VERSION 5.5 ;
NAMESCASESENSITIVE ON ;
BUSBITCHARS "[]" ;
DIVIDERCHAR "/" ;

PROPERTYDEFINITIONS
  LAYER routingPitch REAL ;
END PROPERTYDEFINITIONS

UNITS
  DATABASE MICRONS 1000 ;
END UNITS
MANUFACTURINGGRID 0.01 ;
LAYER POLY1
  TYPE MASTERSLICE ;
END POLY1

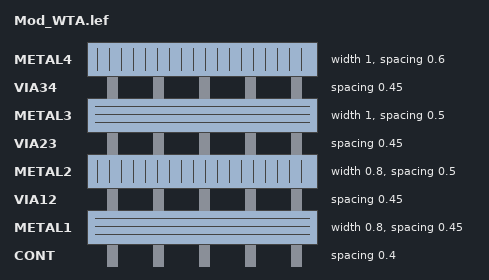
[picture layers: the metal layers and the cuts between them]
LAYER CONT
  TYPE CUT ;
  SPACING 0.4 ;
END CONT

LAYER METAL1
  TYPE ROUTING ;
  DIRECTION HORIZONTAL ;
  PITCH 0 ;
  WIDTH 0.8 ;
  SPACING 0.45 ;
  PROPERTY routingPitch 1.25 ;
END METAL1

LAYER VIA12
  TYPE CUT ;
  SPACING 0.45 ;
END VIA12

LAYER METAL2
  TYPE ROUTING ;
  DIRECTION VERTICAL ;
  PITCH 0 ;
  WIDTH 0.8 ;
  SPACING 0.5 ;
  PROPERTY routingPitch 1.4 ;
END METAL2

LAYER VIA23
  TYPE CUT ;
  SPACING 0.45 ;
END VIA23

LAYER METAL3
  TYPE ROUTING ;
  DIRECTION HORIZONTAL ;
  PITCH 0 ;
  WIDTH 1.0 ;
  SPACING 0.5 ;
  PROPERTY routingPitch 1.25 ;
END METAL3

LAYER VIA34
  TYPE CUT ;
  SPACING 0.45 ;
END VIA34

LAYER METAL4
  TYPE ROUTING ;
  DIRECTION VERTICAL ;
  PITCH 0 ;
  WIDTH 1.0 ;
  SPACING 0.6 ;
  PROPERTY routingPitch 1.4 ;
END METAL4

LAYER OVERLAP
  TYPE OVERLAP ;
END OVERLAP

VIARULE M4_M3 GENERATE
  LAYER METAL3 ;
    ENCLOSURE 0.2 0.2 ;
  LAYER METAL4 ;
    ENCLOSURE 0.15 0.15 ;
  LAYER VIA34 ;
    RECT -0.25 -0.25 0.25 0.25 ;
    SPACING 1 BY 1 ;
END M4_M3

VIARULE M3_M2 GENERATE
  LAYER METAL2 ;
    ENCLOSURE 0.2 0.2 ;
  LAYER METAL3 ;
    ENCLOSURE 0.15 0.15 ;
  LAYER VIA23 ;
    RECT -0.25 -0.25 0.25 0.25 ;
    SPACING 1 BY 1 ;
END M3_M2

VIARULE M2_M1 GENERATE
  LAYER METAL1 ;
    ENCLOSURE 0.2 0.2 ;
  LAYER METAL2 ;
    ENCLOSURE 0.15 0.15 ;
  LAYER VIA12 ;
    RECT -0.25 -0.25 0.25 0.25 ;
    SPACING 1 BY 1 ;
END M2_M1

VIARULE M1_POLY1 GENERATE
  LAYER POLY1 ;
    ENCLOSURE 0.2 0.2 ;
  LAYER METAL1 ;
    ENCLOSURE 0.15 0.15 ;
  LAYER CONT ;
    RECT -0.2 -0.2 0.2 0.2 ;
    SPACING 1 BY 1 ;
END M1_POLY1

VIA M1_POLY1
  LAYER CONT ;
    RECT -0.2 -0.2 0.2 0.2 ;
  LAYER POLY1 ;
    RECT -0.4 -0.4 0.4 0.4 ;
  LAYER METAL1 ;
    RECT -0.35 -0.35 0.35 0.35 ;
END M1_POLY1

VIA M2_M1
  LAYER VIA12 ;
    RECT -0.25 -0.25 0.25 0.25 ;
  LAYER METAL2 ;
    RECT -0.4 -0.4 0.4 0.4 ;
  LAYER METAL1 ;
    RECT -0.45 -0.45 0.45 0.45 ;
END M2_M1

VIA M3_M2
  LAYER VIA23 ;
    RECT -0.25 -0.25 0.25 0.25 ;
  LAYER METAL3 ;
    RECT -0.4 -0.4 0.4 0.4 ;
  LAYER METAL2 ;
    RECT -0.45 -0.45 0.45 0.45 ;
END M3_M2

VIA M4_M3
  LAYER VIA34 ;
    RECT -0.25 -0.25 0.25 0.25 ;
  LAYER METAL4 ;
    RECT -0.4 -0.4 0.4 0.4 ;
  LAYER METAL3 ;
    RECT -0.45 -0.45 0.45 0.45 ;
END M4_M3


MACRO Modulation
  PIN VOUT<279>
    DIRECTION INOUT ;
    USE SIGNAL ;
    PORT
      LAYER METAL3 ;
        RECT 4828.05 108.45 4828.85 109.25 ;
    END
  END VOUT<279>
  PIN VOUT<275>
    DIRECTION INOUT ;
    USE SIGNAL ;
    PORT
      LAYER METAL3 ;
        RECT 4828.05 130.45 4828.85 131.25 ;
    END
  END VOUT<275>
  PIN VOUT<271>
    DIRECTION INOUT ;
    USE SIGNAL ;
    PORT
      LAYER METAL3 ;
        RECT 4828.05 152.45 4828.85 153.25 ;
    END
  END VOUT<271>
  PIN VOUT<267>
    DIRECTION INOUT ;
    USE SIGNAL ;
    PORT
      LAYER METAL3 ;
        RECT 4828.05 174.45 4828.85 175.25 ;
    END
  END VOUT<267>
  PIN VOUT<263>
    DIRECTION INOUT ;
    USE SIGNAL ;
    PORT
      LAYER METAL3 ;
        RECT 4828.05 196.45 4828.85 197.25 ;
    END
  END VOUT<263>
  PIN VOUT<259>
    DIRECTION INOUT ;
    USE SIGNAL ;
    PORT
      LAYER METAL3 ;
        RECT 4828.05 218.45 4828.85 219.25 ;
    END
  END VOUT<259>
  PIN VOUT<255>
    DIRECTION INOUT ;
    USE SIGNAL ;
    PORT
      LAYER METAL3 ;
        RECT 4828.05 240.45 4828.85 241.25 ;
    END
  END VOUT<255>
  PIN VOUT<251>
    DIRECTION INOUT ;
    USE SIGNAL ;
    PORT
      LAYER METAL3 ;
        RECT 4828.05 262.45 4828.85 263.25 ;
    END
  END VOUT<251>
  PIN VOUT<247>
    DIRECTION INOUT ;
    USE SIGNAL ;
    PORT
      LAYER METAL3 ;
        RECT 4828.05 284.45 4828.85 285.25 ;
    END
  END VOUT<247>
  PIN VOUT<243>
    DIRECTION INOUT ;
    USE SIGNAL ;
    PORT
      LAYER METAL3 ;
        RECT 4828.05 306.45 4828.85 307.25 ;
    END
  END VOUT<243>
  PIN VOUT<239>
    DIRECTION INOUT ;
    USE SIGNAL ;
    PORT
      LAYER METAL3 ;
        RECT 4828.05 328.45 4828.85 329.25 ;
    END
  END VOUT<239>
  PIN VOUT<235>
    DIRECTION INOUT ;
    USE SIGNAL ;
    PORT
      LAYER METAL3 ;
        RECT 4828.05 350.45 4828.85 351.25 ;
    END
  END VOUT<235>
  PIN VOUT<231>
    DIRECTION INOUT ;
    USE SIGNAL ;
    PORT
      LAYER METAL3 ;
        RECT 4828.05 372.45 4828.85 373.25 ;
    END
  END VOUT<231>
  PIN VOUT<227>
    DIRECTION INOUT ;
    USE SIGNAL ;
    PORT
      LAYER METAL3 ;
        RECT 4828.05 394.45 4828.85 395.25 ;
    END
  END VOUT<227>
  PIN VOUT<223>
    DIRECTION INOUT ;
    USE SIGNAL ;
    PORT
      LAYER METAL3 ;
        RECT 4828.05 416.45 4828.85 417.25 ;
    END
  END VOUT<223>
  PIN VOUT<219>
    DIRECTION INOUT ;
    USE SIGNAL ;
    PORT
      LAYER METAL3 ;
        RECT 4828.05 438.45 4828.85 439.25 ;
    END
  END VOUT<219>
  PIN VOUT<215>
    DIRECTION INOUT ;
    USE SIGNAL ;
    PORT
      LAYER METAL3 ;
        RECT 4828.05 460.45 4828.85 461.25 ;
    END
  END VOUT<215>
  PIN VOUT<211>
    DIRECTION INOUT ;
    USE SIGNAL ;
    PORT
      LAYER METAL3 ;
        RECT 4828.05 482.45 4828.85 483.25 ;
    END
  END VOUT<211>
  PIN VOUT<207>
    DIRECTION INOUT ;
    USE SIGNAL ;
    PORT
      LAYER METAL3 ;
        RECT 4828.05 504.45 4828.85 505.25 ;
    END
  END VOUT<207>
  PIN VOUT<203>
    DIRECTION INOUT ;
    USE SIGNAL ;
    PORT
      LAYER METAL3 ;
        RECT 4828.05 526.45 4828.85 527.25 ;
    END
  END VOUT<203>
  PIN VOUT<199>
    DIRECTION INOUT ;
    USE SIGNAL ;
    PORT
      LAYER METAL3 ;
        RECT 4828.05 548.45 4828.85 549.25 ;
    END
  END VOUT<199>
  PIN VOUT<195>
    DIRECTION INOUT ;
    USE SIGNAL ;
    PORT
      LAYER METAL3 ;
        RECT 4828.05 570.45 4828.85 571.25 ;
    END
  END VOUT<195>
  PIN VOUT<191>
    DIRECTION INOUT ;
    USE SIGNAL ;
    PORT
      LAYER METAL3 ;
        RECT 4828.05 592.45 4828.85 593.25 ;
    END
  END VOUT<191>
  PIN VOUT<187>
    DIRECTION INOUT ;
    USE SIGNAL ;
    PORT
      LAYER METAL3 ;
        RECT 4828.05 614.45 4828.85 615.25 ;
    END
  END VOUT<187>
  PIN VOUT<183>
    DIRECTION INOUT ;
    USE SIGNAL ;
    PORT
      LAYER METAL3 ;
        RECT 4828.05 636.45 4828.85 637.25 ;
    END
  END VOUT<183>
  PIN VOUT<179>
    DIRECTION INOUT ;
    USE SIGNAL ;
    PORT
      LAYER METAL3 ;
        RECT 4828.05 658.45 4828.85 659.25 ;
    END
  END VOUT<179>
  PIN VOUT<175>
    DIRECTION INOUT ;
    USE SIGNAL ;
    PORT
      LAYER METAL3 ;
        RECT 4828.05 680.45 4828.85 681.25 ;
    END
  END VOUT<175>
  PIN VOUT<171>
    DIRECTION INOUT ;
    USE SIGNAL ;
    PORT
      LAYER METAL3 ;
        RECT 4828.05 702.45 4828.85 703.25 ;
    END
  END VOUT<171>
  PIN VOUT<167>
    DIRECTION INOUT ;
    USE SIGNAL ;
    PORT
      LAYER METAL3 ;
        RECT 4828.05 724.45 4828.85 725.25 ;
    END
  END VOUT<167>
  PIN VOUT<163>
    DIRECTION INOUT ;
    USE SIGNAL ;
    PORT
      LAYER METAL3 ;
        RECT 4828.05 746.45 4828.85 747.25 ;
    END
  END VOUT<163>
  PIN VOUT<159>
    DIRECTION INOUT ;
    USE SIGNAL ;
    PORT
      LAYER METAL3 ;
        RECT 4828.05 768.45 4828.85 769.25 ;
    END
  END VOUT<159>
  PIN VOUT<155>
    DIRECTION INOUT ;
    USE SIGNAL ;
    PORT
      LAYER METAL3 ;
        RECT 4828.05 790.45 4828.85 791.25 ;
    END
  END VOUT<155>
  PIN VOUT<151>
    DIRECTION INOUT ;
    USE SIGNAL ;
    PORT
      LAYER METAL3 ;
        RECT 4828.05 812.45 4828.85 813.25 ;
    END
  END VOUT<151>
  PIN VOUT<147>
    DIRECTION INOUT ;
    USE SIGNAL ;
    PORT
      LAYER METAL3 ;
        RECT 4828.05 834.45 4828.85 835.25 ;
    END
  END VOUT<147>
  PIN VOUT<143>
    DIRECTION INOUT ;
    USE SIGNAL ;
    PORT
      LAYER METAL3 ;
        RECT 4828.05 856.45 4828.85 857.25 ;
    END
  END VOUT<143>
  PIN VOUT<139>
    DIRECTION INOUT ;
    USE SIGNAL ;
    PORT
      LAYER METAL3 ;
        RECT 4828.05 878.45 4828.85 879.25 ;
    END
  END VOUT<139>
  PIN VOUT<135>
    DIRECTION INOUT ;
    USE SIGNAL ;
    PORT
      LAYER METAL3 ;
        RECT 4828.05 900.45 4828.85 901.25 ;
    END
  END VOUT<135>
  PIN VOUT<131>
    DIRECTION INOUT ;
    USE SIGNAL ;
    PORT
      LAYER METAL3 ;
        RECT 4828.05 922.45 4828.85 923.25 ;
    END
  END VOUT<131>
  PIN VOUT<127>
    DIRECTION INOUT ;
    USE SIGNAL ;
    PORT
      LAYER METAL3 ;
        RECT 4828.05 944.45 4828.85 945.25 ;
    END
  END VOUT<127>
  PIN VOUT<123>
    DIRECTION INOUT ;
    USE SIGNAL ;
    PORT
      LAYER METAL3 ;
        RECT 4828.05 966.45 4828.85 967.25 ;
    END
  END VOUT<123>
  PIN VOUT<119>
    DIRECTION INOUT ;
    USE SIGNAL ;
    PORT
      LAYER METAL3 ;
        RECT 4828.05 988.45 4828.85 989.25 ;
    END
  END VOUT<119>
  PIN VOUT<115>
    DIRECTION INOUT ;
    USE SIGNAL ;
    PORT
      LAYER METAL3 ;
        RECT 4828.05 1010.45 4828.85 1011.25 ;
    END
  END VOUT<115>
  PIN VOUT<111>
    DIRECTION INOUT ;
    USE SIGNAL ;
    PORT
      LAYER METAL3 ;
        RECT 4828.05 1032.45 4828.85 1033.25 ;
    END
  END VOUT<111>
  PIN VOUT<107>
    DIRECTION INOUT ;
    USE SIGNAL ;
    PORT
      LAYER METAL3 ;
        RECT 4828.05 1054.45 4828.85 1055.25 ;
    END
  END VOUT<107>
  PIN VOUT<103>
    DIRECTION INOUT ;
    USE SIGNAL ;
    PORT
      LAYER METAL3 ;
        RECT 4828.05 1076.45 4828.85 1077.25 ;
    END
  END VOUT<103>
  PIN VOUT<99>
    DIRECTION INOUT ;
    USE SIGNAL ;
    PORT
      LAYER METAL3 ;
        RECT 4828.05 1098.45 4828.85 1099.25 ;
    END
  END VOUT<99>
  PIN VOUT<95>
    DIRECTION INOUT ;
    USE SIGNAL ;
    PORT
      LAYER METAL3 ;
        RECT 4828.05 1120.45 4828.85 1121.25 ;
    END
  END VOUT<95>
  PIN VOUT<91>
    DIRECTION INOUT ;
    USE SIGNAL ;
    PORT
      LAYER METAL3 ;
        RECT 4828.05 1142.45 4828.85 1143.25 ;
    END
  END VOUT<91>
  PIN VOUT<87>
    DIRECTION INOUT ;
    USE SIGNAL ;
    PORT
      LAYER METAL3 ;
        RECT 4828.05 1164.45 4828.85 1165.25 ;
    END
  END VOUT<87>
  PIN VOUT<83>
    DIRECTION INOUT ;
    USE SIGNAL ;
    PORT
      LAYER METAL3 ;
        RECT 4828.05 1186.45 4828.85 1187.25 ;
    END
  END VOUT<83>
  PIN VOUT<79>
    DIRECTION INOUT ;
    USE SIGNAL ;
    PORT
      LAYER METAL3 ;
        RECT 4828.05 1208.45 4828.85 1209.25 ;
    END
  END VOUT<79>
  PIN VOUT<75>
    DIRECTION INOUT ;
    USE SIGNAL ;
    PORT
      LAYER METAL3 ;
        RECT 4828.05 1230.45 4828.85 1231.25 ;
    END
  END VOUT<75>
  PIN VOUT<71>
    DIRECTION INOUT ;
    USE SIGNAL ;
    PORT
      LAYER METAL3 ;
        RECT 4828.05 1252.45 4828.85 1253.25 ;
    END
  END VOUT<71>
  PIN VOUT<67>
    DIRECTION INOUT ;
    USE SIGNAL ;
    PORT
      LAYER METAL3 ;
        RECT 4828.05 1274.45 4828.85 1275.25 ;
    END
  END VOUT<67>
  PIN VOUT<63>
    DIRECTION INOUT ;
    USE SIGNAL ;
    PORT
      LAYER METAL3 ;
        RECT 4828.05 1296.45 4828.85 1297.25 ;
    END
  END VOUT<63>
  PIN VOUT<59>
    DIRECTION INOUT ;
    USE SIGNAL ;
    PORT
      LAYER METAL3 ;
        RECT 4828.05 1318.45 4828.85 1319.25 ;
    END
  END VOUT<59>
  PIN VOUT<55>
    DIRECTION INOUT ;
    USE SIGNAL ;
    PORT
      LAYER METAL3 ;
        RECT 4828.05 1340.45 4828.85 1341.25 ;
    END
  END VOUT<55>
  PIN VOUT<51>
    DIRECTION INOUT ;
    USE SIGNAL ;
    PORT
      LAYER METAL3 ;
        RECT 4828.05 1362.45 4828.85 1363.25 ;
    END
  END VOUT<51>
  PIN VOUT<47>
    DIRECTION INOUT ;
    USE SIGNAL ;
    PORT
      LAYER METAL3 ;
        RECT 4828.05 1384.45 4828.85 1385.25 ;
    END
  END VOUT<47>
  PIN VOUT<43>
    DIRECTION INOUT ;
    USE SIGNAL ;
    PORT
      LAYER METAL3 ;
        RECT 4828.05 1406.45 4828.85 1407.25 ;
    END
  END VOUT<43>
  PIN VOUT<39>
    DIRECTION INOUT ;
    USE SIGNAL ;
    PORT
      LAYER METAL3 ;
        RECT 4828.05 1428.45 4828.85 1429.25 ;
    END
  END VOUT<39>
  PIN VOUT<35>
    DIRECTION INOUT ;
    USE SIGNAL ;
    PORT
      LAYER METAL3 ;
        RECT 4828.05 1450.45 4828.85 1451.25 ;
    END
  END VOUT<35>
  PIN VOUT<31>
    DIRECTION INOUT ;
    USE SIGNAL ;
    PORT
      LAYER METAL3 ;
        RECT 4828.05 1472.45 4828.85 1473.25 ;
    END
  END VOUT<31>
  PIN VOUT<27>
    DIRECTION INOUT ;
    USE SIGNAL ;
    PORT
      LAYER METAL3 ;
        RECT 4828.05 1494.45 4828.85 1495.25 ;
    END
  END VOUT<27>
  PIN VOUT<23>
    DIRECTION INOUT ;
    USE SIGNAL ;
    PORT
      LAYER METAL3 ;
        RECT 4828.05 1516.45 4828.85 1517.25 ;
    END
  END VOUT<23>
  PIN VOUT<19>
    DIRECTION INOUT ;
    USE SIGNAL ;
    PORT
      LAYER METAL3 ;
        RECT 4828.05 1538.45 4828.85 1539.25 ;
    END
  END VOUT<19>
  PIN VOUT<15>
    DIRECTION INOUT ;
    USE SIGNAL ;
    PORT
      LAYER METAL3 ;
        RECT 4828.05 1560.45 4828.85 1561.25 ;
    END
  END VOUT<15>
  PIN VOUT<11>
    DIRECTION INOUT ;
    USE SIGNAL ;
    PORT
      LAYER METAL3 ;
        RECT 4828.05 1582.45 4828.85 1583.25 ;
    END
  END VOUT<11>
  PIN VOUT<7>
    DIRECTION INOUT ;
    USE SIGNAL ;
    PORT
      LAYER METAL3 ;
        RECT 4828.05 1604.45 4828.85 1605.25 ;
    END
  END VOUT<7>
  PIN VOUT<3>
    DIRECTION INOUT ;
    USE SIGNAL ;
    PORT
      LAYER METAL3 ;
        RECT 4828.05 1626.45 4828.85 1627.25 ;
    END
  END VOUT<3>
  PIN VOUT<278>
    DIRECTION INOUT ;
    USE SIGNAL ;
    PORT
      LAYER METAL3 ;
        RECT 4828.05 111.25 4828.85 112.05 ;
    END
  END VOUT<278>
  PIN VOUT<274>
    DIRECTION INOUT ;
    USE SIGNAL ;
    PORT
      LAYER METAL3 ;
        RECT 4828.05 133.25 4828.85 134.05 ;
    END
  END VOUT<274>
  PIN VOUT<270>
    DIRECTION INOUT ;
    USE SIGNAL ;
    PORT
      LAYER METAL3 ;
        RECT 4828.05 155.25 4828.85 156.05 ;
    END
  END VOUT<270>
  PIN VOUT<266>
    DIRECTION INOUT ;
    USE SIGNAL ;
    PORT
      LAYER METAL3 ;
        RECT 4828.05 177.25 4828.85 178.05 ;
    END
  END VOUT<266>
  PIN VOUT<262>
    DIRECTION INOUT ;
    USE SIGNAL ;
    PORT
      LAYER METAL3 ;
        RECT 4828.05 199.25 4828.85 200.05 ;
    END
  END VOUT<262>
  PIN VOUT<258>
    DIRECTION INOUT ;
    USE SIGNAL ;
    PORT
      LAYER METAL3 ;
        RECT 4828.05 221.25 4828.85 222.05 ;
    END
  END VOUT<258>
  PIN VOUT<254>
    DIRECTION INOUT ;
    USE SIGNAL ;
    PORT
      LAYER METAL3 ;
        RECT 4828.05 243.25 4828.85 244.05 ;
    END
  END VOUT<254>
  PIN VOUT<250>
    DIRECTION INOUT ;
    USE SIGNAL ;
    PORT
      LAYER METAL3 ;
        RECT 4828.05 265.25 4828.85 266.05 ;
    END
  END VOUT<250>
  PIN VOUT<246>
    DIRECTION INOUT ;
    USE SIGNAL ;
    PORT
      LAYER METAL3 ;
        RECT 4828.05 287.25 4828.85 288.05 ;
    END
  END VOUT<246>
  PIN VOUT<242>
    DIRECTION INOUT ;
    USE SIGNAL ;
    PORT
      LAYER METAL3 ;
        RECT 4828.05 309.25 4828.85 310.05 ;
    END
  END VOUT<242>
  PIN VOUT<238>
    DIRECTION INOUT ;
    USE SIGNAL ;
    PORT
      LAYER METAL3 ;
        RECT 4828.05 331.25 4828.85 332.05 ;
    END
  END VOUT<238>
  PIN VOUT<234>
    DIRECTION INOUT ;
    USE SIGNAL ;
    PORT
      LAYER METAL3 ;
        RECT 4828.05 353.25 4828.85 354.05 ;
    END
  END VOUT<234>
  PIN VOUT<230>
    DIRECTION INOUT ;
    USE SIGNAL ;
    PORT
      LAYER METAL3 ;
        RECT 4828.05 375.25 4828.85 376.05 ;
    END
  END VOUT<230>
  PIN VOUT<226>
    DIRECTION INOUT ;
    USE SIGNAL ;
    PORT
      LAYER METAL3 ;
        RECT 4828.05 397.25 4828.85 398.05 ;
    END
  END VOUT<226>
  PIN VOUT<222>
    DIRECTION INOUT ;
    USE SIGNAL ;
    PORT
      LAYER METAL3 ;
        RECT 4828.05 419.25 4828.85 420.05 ;
    END
  END VOUT<222>
  PIN VOUT<218>
    DIRECTION INOUT ;
    USE SIGNAL ;
    PORT
      LAYER METAL3 ;
        RECT 4828.05 441.25 4828.85 442.05 ;
    END
  END VOUT<218>
  PIN VOUT<214>
    DIRECTION INOUT ;
    USE SIGNAL ;
    PORT
      LAYER METAL3 ;
        RECT 4828.05 463.25 4828.85 464.05 ;
    END
  END VOUT<214>
  PIN VOUT<210>
    DIRECTION INOUT ;
    USE SIGNAL ;
    PORT
      LAYER METAL3 ;
        RECT 4828.05 485.25 4828.85 486.05 ;
    END
  END VOUT<210>
  PIN VOUT<206>
    DIRECTION INOUT ;
    USE SIGNAL ;
    PORT
      LAYER METAL3 ;
        RECT 4828.05 507.25 4828.85 508.05 ;
    END
  END VOUT<206>
  PIN VOUT<202>
    DIRECTION INOUT ;
    USE SIGNAL ;
    PORT
      LAYER METAL3 ;
        RECT 4828.05 529.25 4828.85 530.05 ;
    END
  END VOUT<202>
  PIN VOUT<198>
    DIRECTION INOUT ;
    USE SIGNAL ;
    PORT
      LAYER METAL3 ;
        RECT 4828.05 551.25 4828.85 552.05 ;
    END
  END VOUT<198>
  PIN VOUT<194>
    DIRECTION INOUT ;
    USE SIGNAL ;
    PORT
      LAYER METAL3 ;
        RECT 4828.05 573.25 4828.85 574.05 ;
    END
  END VOUT<194>
  PIN VOUT<190>
    DIRECTION INOUT ;
    USE SIGNAL ;
    PORT
      LAYER METAL3 ;
        RECT 4828.05 595.25 4828.85 596.05 ;
    END
  END VOUT<190>
  PIN VOUT<186>
    DIRECTION INOUT ;
    USE SIGNAL ;
    PORT
      LAYER METAL3 ;
        RECT 4828.05 617.25 4828.85 618.05 ;
    END
  END VOUT<186>
  PIN VOUT<182>
    DIRECTION INOUT ;
    USE SIGNAL ;
    PORT
      LAYER METAL3 ;
        RECT 4828.05 639.25 4828.85 640.05 ;
    END
  END VOUT<182>
  PIN VOUT<178>
    DIRECTION INOUT ;
    USE SIGNAL ;
    PORT
      LAYER METAL3 ;
        RECT 4828.05 661.25 4828.85 662.05 ;
    END
  END VOUT<178>
  PIN VOUT<174>
    DIRECTION INOUT ;
    USE SIGNAL ;
    PORT
      LAYER METAL3 ;
        RECT 4828.05 683.25 4828.85 684.05 ;
    END
  END VOUT<174>
  PIN VOUT<170>
    DIRECTION INOUT ;
    USE SIGNAL ;
    PORT
      LAYER METAL3 ;
        RECT 4828.05 705.25 4828.85 706.05 ;
    END
  END VOUT<170>
  PIN VOUT<166>
    DIRECTION INOUT ;
    USE SIGNAL ;
    PORT
      LAYER METAL3 ;
        RECT 4828.05 727.25 4828.85 728.05 ;
    END
  END VOUT<166>
  PIN VOUT<162>
    DIRECTION INOUT ;
    USE SIGNAL ;
    PORT
      LAYER METAL3 ;
        RECT 4828.05 749.25 4828.85 750.05 ;
    END
  END VOUT<162>
  PIN VOUT<158>
    DIRECTION INOUT ;
    USE SIGNAL ;
    PORT
      LAYER METAL3 ;
        RECT 4828.05 771.25 4828.85 772.05 ;
    END
  END VOUT<158>
  PIN VOUT<154>
    DIRECTION INOUT ;
    USE SIGNAL ;
    PORT
      LAYER METAL3 ;
        RECT 4828.05 793.25 4828.85 794.05 ;
    END
  END VOUT<154>
  PIN VOUT<150>
    DIRECTION INOUT ;
    USE SIGNAL ;
    PORT
      LAYER METAL3 ;
        RECT 4828.05 815.25 4828.85 816.05 ;
    END
  END VOUT<150>
  PIN VOUT<146>
    DIRECTION INOUT ;
    USE SIGNAL ;
    PORT
      LAYER METAL3 ;
        RECT 4828.05 837.25 4828.85 838.05 ;
    END
  END VOUT<146>
  PIN VOUT<142>
    DIRECTION INOUT ;
    USE SIGNAL ;
    PORT
      LAYER METAL3 ;
        RECT 4828.05 859.25 4828.85 860.05 ;
    END
  END VOUT<142>
  PIN VOUT<138>
    DIRECTION INOUT ;
    USE SIGNAL ;
    PORT
      LAYER METAL3 ;
        RECT 4828.05 881.25 4828.85 882.05 ;
    END
  END VOUT<138>
  PIN VOUT<134>
    DIRECTION INOUT ;
    USE SIGNAL ;
    PORT
      LAYER METAL3 ;
        RECT 4828.05 903.25 4828.85 904.05 ;
    END
  END VOUT<134>
  PIN VOUT<130>
    DIRECTION INOUT ;
    USE SIGNAL ;
    PORT
      LAYER METAL3 ;
        RECT 4828.05 925.25 4828.85 926.05 ;
    END
  END VOUT<130>
  PIN VOUT<126>
    DIRECTION INOUT ;
    USE SIGNAL ;
    PORT
      LAYER METAL3 ;
        RECT 4828.05 947.25 4828.85 948.05 ;
    END
  END VOUT<126>
  PIN VOUT<122>
    DIRECTION INOUT ;
    USE SIGNAL ;
    PORT
      LAYER METAL3 ;
        RECT 4828.05 969.25 4828.85 970.05 ;
    END
  END VOUT<122>
  PIN VOUT<118>
    DIRECTION INOUT ;
    USE SIGNAL ;
    PORT
      LAYER METAL3 ;
        RECT 4828.05 991.25 4828.85 992.05 ;
    END
  END VOUT<118>
  PIN VOUT<114>
    DIRECTION INOUT ;
    USE SIGNAL ;
    PORT
      LAYER METAL3 ;
        RECT 4828.05 1013.25 4828.85 1014.05 ;
    END
  END VOUT<114>
  PIN VOUT<110>
    DIRECTION INOUT ;
    USE SIGNAL ;
    PORT
      LAYER METAL3 ;
        RECT 4828.05 1035.25 4828.85 1036.05 ;
    END
  END VOUT<110>
  PIN VOUT<106>
    DIRECTION INOUT ;
    USE SIGNAL ;
    PORT
      LAYER METAL3 ;
        RECT 4828.05 1057.25 4828.85 1058.05 ;
    END
  END VOUT<106>
  PIN VOUT<102>
    DIRECTION INOUT ;
    USE SIGNAL ;
    PORT
      LAYER METAL3 ;
        RECT 4828.05 1079.25 4828.85 1080.05 ;
    END
  END VOUT<102>
  PIN VOUT<98>
    DIRECTION INOUT ;
    USE SIGNAL ;
    PORT
      LAYER METAL3 ;
        RECT 4828.05 1101.25 4828.85 1102.05 ;
    END
  END VOUT<98>
  PIN VOUT<94>
    DIRECTION INOUT ;
    USE SIGNAL ;
    PORT
      LAYER METAL3 ;
        RECT 4828.05 1123.25 4828.85 1124.05 ;
    END
  END VOUT<94>
  PIN VOUT<90>
    DIRECTION INOUT ;
    USE SIGNAL ;
    PORT
      LAYER METAL3 ;
        RECT 4828.05 1145.25 4828.85 1146.05 ;
    END
  END VOUT<90>
  PIN VOUT<86>
    DIRECTION INOUT ;
    USE SIGNAL ;
    PORT
      LAYER METAL3 ;
        RECT 4828.05 1167.25 4828.85 1168.05 ;
    END
  END VOUT<86>
  PIN VOUT<82>
    DIRECTION INOUT ;
    USE SIGNAL ;
    PORT
      LAYER METAL3 ;
        RECT 4828.05 1189.25 4828.85 1190.05 ;
    END
  END VOUT<82>
  PIN VOUT<78>
    DIRECTION INOUT ;
    USE SIGNAL ;
    PORT
      LAYER METAL3 ;
        RECT 4828.05 1211.25 4828.85 1212.05 ;
    END
  END VOUT<78>
  PIN VOUT<74>
    DIRECTION INOUT ;
    USE SIGNAL ;
    PORT
      LAYER METAL3 ;
        RECT 4828.05 1233.25 4828.85 1234.05 ;
    END
  END VOUT<74>
  PIN VOUT<70>
    DIRECTION INOUT ;
    USE SIGNAL ;
    PORT
      LAYER METAL3 ;
        RECT 4828.05 1255.25 4828.85 1256.05 ;
    END
  END VOUT<70>
  PIN VOUT<66>
    DIRECTION INOUT ;
    USE SIGNAL ;
    PORT
      LAYER METAL3 ;
        RECT 4828.05 1277.25 4828.85 1278.05 ;
    END
  END VOUT<66>
  PIN VOUT<62>
    DIRECTION INOUT ;
    USE SIGNAL ;
    PORT
      LAYER METAL3 ;
        RECT 4828.05 1299.25 4828.85 1300.05 ;
    END
  END VOUT<62>
  PIN VOUT<58>
    DIRECTION INOUT ;
    USE SIGNAL ;
    PORT
      LAYER METAL3 ;
        RECT 4828.05 1321.25 4828.85 1322.05 ;
    END
  END VOUT<58>
  PIN VOUT<54>
    DIRECTION INOUT ;
    USE SIGNAL ;
    PORT
      LAYER METAL3 ;
        RECT 4828.05 1343.25 4828.85 1344.05 ;
    END
  END VOUT<54>
  PIN VOUT<50>
    DIRECTION INOUT ;
    USE SIGNAL ;
    PORT
      LAYER METAL3 ;
        RECT 4828.05 1365.25 4828.85 1366.05 ;
    END
  END VOUT<50>
  PIN VOUT<46>
    DIRECTION INOUT ;
    USE SIGNAL ;
    PORT
      LAYER METAL3 ;
        RECT 4828.05 1387.25 4828.85 1388.05 ;
    END
  END VOUT<46>
  PIN VOUT<42>
    DIRECTION INOUT ;
    USE SIGNAL ;
    PORT
      LAYER METAL3 ;
        RECT 4828.05 1409.25 4828.85 1410.05 ;
    END
  END VOUT<42>
  PIN VOUT<38>
    DIRECTION INOUT ;
    USE SIGNAL ;
    PORT
      LAYER METAL3 ;
        RECT 4828.05 1431.25 4828.85 1432.05 ;
    END
  END VOUT<38>
  PIN VOUT<34>
    DIRECTION INOUT ;
    USE SIGNAL ;
    PORT
      LAYER METAL3 ;
        RECT 4828.05 1453.25 4828.85 1454.05 ;
    END
  END VOUT<34>
  PIN VOUT<30>
    DIRECTION INOUT ;
    USE SIGNAL ;
    PORT
      LAYER METAL3 ;
        RECT 4828.05 1475.25 4828.85 1476.05 ;
    END
  END VOUT<30>
  PIN VOUT<26>
    DIRECTION INOUT ;
    USE SIGNAL ;
    PORT
      LAYER METAL3 ;
        RECT 4828.05 1497.25 4828.85 1498.05 ;
    END
  END VOUT<26>
  PIN VOUT<22>
    DIRECTION INOUT ;
    USE SIGNAL ;
    PORT
      LAYER METAL3 ;
        RECT 4828.05 1519.25 4828.85 1520.05 ;
    END
  END VOUT<22>
  PIN VOUT<18>
    DIRECTION INOUT ;
    USE SIGNAL ;
    PORT
      LAYER METAL3 ;
        RECT 4828.05 1541.25 4828.85 1542.05 ;
    END
  END VOUT<18>
  PIN VOUT<14>
    DIRECTION INOUT ;
    USE SIGNAL ;
    PORT
      LAYER METAL3 ;
        RECT 4828.05 1563.25 4828.85 1564.05 ;
    END
  END VOUT<14>
  PIN VOUT<10>
    DIRECTION INOUT ;
    USE SIGNAL ;
    PORT
      LAYER METAL3 ;
        RECT 4828.05 1585.25 4828.85 1586.05 ;
    END
  END VOUT<10>
  PIN VOUT<6>
    DIRECTION INOUT ;
    USE SIGNAL ;
    PORT
      LAYER METAL3 ;
        RECT 4828.05 1607.25 4828.85 1608.05 ;
    END
  END VOUT<6>
  PIN VOUT<2>
    DIRECTION INOUT ;
    USE SIGNAL ;
    PORT
      LAYER METAL3 ;
        RECT 4828.05 1629.25 4828.85 1630.05 ;
    END
  END VOUT<2>
  PIN VOUT<277>
    DIRECTION INOUT ;
    USE SIGNAL ;
    PORT
      LAYER METAL3 ;
        RECT 4828.05 115.45 4828.85 116.25 ;
    END
  END VOUT<277>
  PIN VOUT<273>
    DIRECTION INOUT ;
    USE SIGNAL ;
    PORT
      LAYER METAL3 ;
        RECT 4828.05 137.45 4828.85 138.25 ;
    END
  END VOUT<273>
  PIN VOUT<269>
    DIRECTION INOUT ;
    USE SIGNAL ;
    PORT
      LAYER METAL3 ;
        RECT 4828.05 159.45 4828.85 160.25 ;
    END
  END VOUT<269>
  PIN VOUT<265>
    DIRECTION INOUT ;
    USE SIGNAL ;
    PORT
      LAYER METAL3 ;
        RECT 4828.05 181.45 4828.85 182.25 ;
    END
  END VOUT<265>
  PIN VOUT<261>
    DIRECTION INOUT ;
    USE SIGNAL ;
    PORT
      LAYER METAL3 ;
        RECT 4828.05 203.45 4828.85 204.25 ;
    END
  END VOUT<261>
  PIN VOUT<257>
    DIRECTION INOUT ;
    USE SIGNAL ;
    PORT
      LAYER METAL3 ;
        RECT 4828.05 225.45 4828.85 226.25 ;
    END
  END VOUT<257>
  PIN VOUT<253>
    DIRECTION INOUT ;
    USE SIGNAL ;
    PORT
      LAYER METAL3 ;
        RECT 4828.05 247.45 4828.85 248.25 ;
    END
  END VOUT<253>
  PIN VOUT<249>
    DIRECTION INOUT ;
    USE SIGNAL ;
    PORT
      LAYER METAL3 ;
        RECT 4828.05 269.45 4828.85 270.25 ;
    END
  END VOUT<249>
  PIN VOUT<245>
    DIRECTION INOUT ;
    USE SIGNAL ;
    PORT
      LAYER METAL3 ;
        RECT 4828.05 291.45 4828.85 292.25 ;
    END
  END VOUT<245>
  PIN VOUT<241>
    DIRECTION INOUT ;
    USE SIGNAL ;
    PORT
      LAYER METAL3 ;
        RECT 4828.05 313.45 4828.85 314.25 ;
    END
  END VOUT<241>
  PIN VOUT<237>
    DIRECTION INOUT ;
    USE SIGNAL ;
    PORT
      LAYER METAL3 ;
        RECT 4828.05 335.45 4828.85 336.25 ;
    END
  END VOUT<237>
  PIN VOUT<233>
    DIRECTION INOUT ;
    USE SIGNAL ;
    PORT
      LAYER METAL3 ;
        RECT 4828.05 357.45 4828.85 358.25 ;
    END
  END VOUT<233>
  PIN VOUT<229>
    DIRECTION INOUT ;
    USE SIGNAL ;
    PORT
      LAYER METAL3 ;
        RECT 4828.05 379.45 4828.85 380.25 ;
    END
  END VOUT<229>
  PIN VOUT<225>
    DIRECTION INOUT ;
    USE SIGNAL ;
    PORT
      LAYER METAL3 ;
        RECT 4828.05 401.45 4828.85 402.25 ;
    END
  END VOUT<225>
  PIN VOUT<221>
    DIRECTION INOUT ;
    USE SIGNAL ;
    PORT
      LAYER METAL3 ;
        RECT 4828.05 423.45 4828.85 424.25 ;
    END
  END VOUT<221>
  PIN VOUT<217>
    DIRECTION INOUT ;
    USE SIGNAL ;
    PORT
      LAYER METAL3 ;
        RECT 4828.05 445.45 4828.85 446.25 ;
    END
  END VOUT<217>
  PIN VOUT<213>
    DIRECTION INOUT ;
    USE SIGNAL ;
    PORT
      LAYER METAL3 ;
        RECT 4828.05 467.45 4828.85 468.25 ;
    END
  END VOUT<213>
  PIN VOUT<209>
    DIRECTION INOUT ;
    USE SIGNAL ;
    PORT
      LAYER METAL3 ;
        RECT 4828.05 489.45 4828.85 490.25 ;
    END
  END VOUT<209>
  PIN VOUT<205>
    DIRECTION INOUT ;
    USE SIGNAL ;
    PORT
      LAYER METAL3 ;
        RECT 4828.05 511.45 4828.85 512.25 ;
    END
  END VOUT<205>
  PIN VOUT<201>
    DIRECTION INOUT ;
    USE SIGNAL ;
    PORT
      LAYER METAL3 ;
        RECT 4828.05 533.45 4828.85 534.25 ;
    END
  END VOUT<201>
  PIN VOUT<197>
    DIRECTION INOUT ;
    USE SIGNAL ;
    PORT
      LAYER METAL3 ;
        RECT 4828.05 555.45 4828.85 556.25 ;
    END
  END VOUT<197>
  PIN VOUT<193>
    DIRECTION INOUT ;
    USE SIGNAL ;
    PORT
      LAYER METAL3 ;
        RECT 4828.05 577.45 4828.85 578.25 ;
    END
  END VOUT<193>
  PIN VOUT<189>
    DIRECTION INOUT ;
    USE SIGNAL ;
    PORT
      LAYER METAL3 ;
        RECT 4828.05 599.45 4828.85 600.25 ;
    END
  END VOUT<189>
  PIN VOUT<185>
    DIRECTION INOUT ;
    USE SIGNAL ;
    PORT
      LAYER METAL3 ;
        RECT 4828.05 621.45 4828.85 622.25 ;
    END
  END VOUT<185>
  PIN VOUT<181>
    DIRECTION INOUT ;
    USE SIGNAL ;
    PORT
      LAYER METAL3 ;
        RECT 4828.05 643.45 4828.85 644.25 ;
    END
  END VOUT<181>
  PIN VOUT<177>
    DIRECTION INOUT ;
    USE SIGNAL ;
    PORT
      LAYER METAL3 ;
        RECT 4828.05 665.45 4828.85 666.25 ;
    END
  END VOUT<177>
  PIN VOUT<173>
    DIRECTION INOUT ;
    USE SIGNAL ;
    PORT
      LAYER METAL3 ;
        RECT 4828.05 687.45 4828.85 688.25 ;
    END
  END VOUT<173>
  PIN VOUT<169>
    DIRECTION INOUT ;
    USE SIGNAL ;
    PORT
      LAYER METAL3 ;
        RECT 4828.05 709.45 4828.85 710.25 ;
    END
  END VOUT<169>
  PIN VOUT<165>
    DIRECTION INOUT ;
    USE SIGNAL ;
    PORT
      LAYER METAL3 ;
        RECT 4828.05 731.45 4828.85 732.25 ;
    END
  END VOUT<165>
  PIN VOUT<161>
    DIRECTION INOUT ;
    USE SIGNAL ;
    PORT
      LAYER METAL3 ;
        RECT 4828.05 753.45 4828.85 754.25 ;
    END
  END VOUT<161>
  PIN VOUT<157>
    DIRECTION INOUT ;
    USE SIGNAL ;
    PORT
      LAYER METAL3 ;
        RECT 4828.05 775.45 4828.85 776.25 ;
    END
  END VOUT<157>
  PIN VOUT<153>
    DIRECTION INOUT ;
    USE SIGNAL ;
    PORT
      LAYER METAL3 ;
        RECT 4828.05 797.45 4828.85 798.25 ;
    END
  END VOUT<153>
  PIN VOUT<149>
    DIRECTION INOUT ;
    USE SIGNAL ;
    PORT
      LAYER METAL3 ;
        RECT 4828.05 819.45 4828.85 820.25 ;
    END
  END VOUT<149>
  PIN VOUT<145>
    DIRECTION INOUT ;
    USE SIGNAL ;
    PORT
      LAYER METAL3 ;
        RECT 4828.05 841.45 4828.85 842.25 ;
    END
  END VOUT<145>
  PIN VOUT<141>
    DIRECTION INOUT ;
    USE SIGNAL ;
    PORT
      LAYER METAL3 ;
        RECT 4828.05 863.45 4828.85 864.25 ;
    END
  END VOUT<141>
  PIN VOUT<137>
    DIRECTION INOUT ;
    USE SIGNAL ;
    PORT
      LAYER METAL3 ;
        RECT 4828.05 885.45 4828.85 886.25 ;
    END
  END VOUT<137>
  PIN VOUT<133>
    DIRECTION INOUT ;
    USE SIGNAL ;
    PORT
      LAYER METAL3 ;
        RECT 4828.05 907.45 4828.85 908.25 ;
    END
  END VOUT<133>
  PIN VOUT<129>
    DIRECTION INOUT ;
    USE SIGNAL ;
    PORT
      LAYER METAL3 ;
        RECT 4828.05 929.45 4828.85 930.25 ;
    END
  END VOUT<129>
  PIN VOUT<125>
    DIRECTION INOUT ;
    USE SIGNAL ;
    PORT
      LAYER METAL3 ;
        RECT 4828.05 951.45 4828.85 952.25 ;
    END
  END VOUT<125>
  PIN VOUT<121>
    DIRECTION INOUT ;
    USE SIGNAL ;
    PORT
      LAYER METAL3 ;
        RECT 4828.05 973.45 4828.85 974.25 ;
    END
  END VOUT<121>
  PIN VOUT<117>
    DIRECTION INOUT ;
    USE SIGNAL ;
    PORT
      LAYER METAL3 ;
        RECT 4828.05 995.45 4828.85 996.25 ;
    END
  END VOUT<117>
  PIN VOUT<113>
    DIRECTION INOUT ;
    USE SIGNAL ;
    PORT
      LAYER METAL3 ;
        RECT 4828.05 1017.45 4828.85 1018.25 ;
    END
  END VOUT<113>
  PIN VOUT<109>
    DIRECTION INOUT ;
    USE SIGNAL ;
    PORT
      LAYER METAL3 ;
        RECT 4828.05 1039.45 4828.85 1040.25 ;
    END
  END VOUT<109>
  PIN VOUT<105>
    DIRECTION INOUT ;
    USE SIGNAL ;
    PORT
      LAYER METAL3 ;
        RECT 4828.05 1061.45 4828.85 1062.25 ;
    END
  END VOUT<105>
  PIN VOUT<101>
    DIRECTION INOUT ;
    USE SIGNAL ;
    PORT
      LAYER METAL3 ;
        RECT 4828.05 1083.45 4828.85 1084.25 ;
    END
  END VOUT<101>
  PIN VOUT<97>
    DIRECTION INOUT ;
    USE SIGNAL ;
    PORT
      LAYER METAL3 ;
        RECT 4828.05 1105.45 4828.85 1106.25 ;
    END
  END VOUT<97>
  PIN VOUT<93>
    DIRECTION INOUT ;
    USE SIGNAL ;
    PORT
      LAYER METAL3 ;
        RECT 4828.05 1127.45 4828.85 1128.25 ;
    END
  END VOUT<93>
  PIN VOUT<89>
    DIRECTION INOUT ;
    USE SIGNAL ;
    PORT
      LAYER METAL3 ;
        RECT 4828.05 1149.45 4828.85 1150.25 ;
    END
  END VOUT<89>
  PIN VOUT<85>
    DIRECTION INOUT ;
    USE SIGNAL ;
    PORT
      LAYER METAL3 ;
        RECT 4828.05 1171.45 4828.85 1172.25 ;
    END
  END VOUT<85>
  PIN VOUT<81>
    DIRECTION INOUT ;
    USE SIGNAL ;
    PORT
      LAYER METAL3 ;
        RECT 4828.05 1193.45 4828.85 1194.25 ;
    END
  END VOUT<81>
  PIN VOUT<77>
    DIRECTION INOUT ;
    USE SIGNAL ;
    PORT
      LAYER METAL3 ;
        RECT 4828.05 1215.45 4828.85 1216.25 ;
    END
  END VOUT<77>
  PIN VOUT<73>
    DIRECTION INOUT ;
    USE SIGNAL ;
    PORT
      LAYER METAL3 ;
        RECT 4828.05 1237.45 4828.85 1238.25 ;
    END
  END VOUT<73>
  PIN VOUT<69>
    DIRECTION INOUT ;
    USE SIGNAL ;
    PORT
      LAYER METAL3 ;
        RECT 4828.05 1259.45 4828.85 1260.25 ;
    END
  END VOUT<69>
  PIN VOUT<65>
    DIRECTION INOUT ;
    USE SIGNAL ;
    PORT
      LAYER METAL3 ;
        RECT 4828.05 1281.45 4828.85 1282.25 ;
    END
  END VOUT<65>
  PIN VOUT<61>
    DIRECTION INOUT ;
    USE SIGNAL ;
    PORT
      LAYER METAL3 ;
        RECT 4828.05 1303.45 4828.85 1304.25 ;
    END
  END VOUT<61>
  PIN VOUT<57>
    DIRECTION INOUT ;
    USE SIGNAL ;
    PORT
      LAYER METAL3 ;
        RECT 4828.05 1325.45 4828.85 1326.25 ;
    END
  END VOUT<57>
  PIN VOUT<53>
    DIRECTION INOUT ;
    USE SIGNAL ;
    PORT
      LAYER METAL3 ;
        RECT 4828.05 1347.45 4828.85 1348.25 ;
    END
  END VOUT<53>
  PIN VOUT<49>
    DIRECTION INOUT ;
    USE SIGNAL ;
    PORT
      LAYER METAL3 ;
        RECT 4828.05 1369.45 4828.85 1370.25 ;
    END
  END VOUT<49>
  PIN VOUT<45>
    DIRECTION INOUT ;
    USE SIGNAL ;
    PORT
      LAYER METAL3 ;
        RECT 4828.05 1391.45 4828.85 1392.25 ;
    END
  END VOUT<45>
  PIN VOUT<41>
    DIRECTION INOUT ;
    USE SIGNAL ;
    PORT
      LAYER METAL3 ;
        RECT 4828.05 1413.45 4828.85 1414.25 ;
    END
  END VOUT<41>
  PIN VOUT<37>
    DIRECTION INOUT ;
    USE SIGNAL ;
    PORT
      LAYER METAL3 ;
        RECT 4828.05 1435.45 4828.85 1436.25 ;
    END
  END VOUT<37>
  PIN VOUT<33>
    DIRECTION INOUT ;
    USE SIGNAL ;
    PORT
      LAYER METAL3 ;
        RECT 4828.05 1457.45 4828.85 1458.25 ;
    END
  END VOUT<33>
  PIN VOUT<29>
    DIRECTION INOUT ;
    USE SIGNAL ;
    PORT
      LAYER METAL3 ;
        RECT 4828.05 1479.45 4828.85 1480.25 ;
    END
  END VOUT<29>
  PIN VOUT<25>
    DIRECTION INOUT ;
    USE SIGNAL ;
    PORT
      LAYER METAL3 ;
        RECT 4828.05 1501.45 4828.85 1502.25 ;
    END
  END VOUT<25>
  PIN VOUT<21>
    DIRECTION INOUT ;
    USE SIGNAL ;
    PORT
      LAYER METAL3 ;
        RECT 4828.05 1523.45 4828.85 1524.25 ;
    END
  END VOUT<21>
  PIN VOUT<17>
    DIRECTION INOUT ;
    USE SIGNAL ;
    PORT
      LAYER METAL3 ;
        RECT 4828.05 1545.45 4828.85 1546.25 ;
    END
  END VOUT<17>
  PIN VOUT<13>
    DIRECTION INOUT ;
    USE SIGNAL ;
    PORT
      LAYER METAL3 ;
        RECT 4828.05 1567.45 4828.85 1568.25 ;
    END
  END VOUT<13>
  PIN VOUT<9>
    DIRECTION INOUT ;
    USE SIGNAL ;
    PORT
      LAYER METAL3 ;
        RECT 4828.05 1589.45 4828.85 1590.25 ;
    END
  END VOUT<9>
  PIN VOUT<5>
    DIRECTION INOUT ;
    USE SIGNAL ;
    PORT
      LAYER METAL3 ;
        RECT 4828.05 1611.45 4828.85 1612.25 ;
    END
  END VOUT<5>
  PIN VOUT<1>
    DIRECTION INOUT ;
    USE SIGNAL ;
    PORT
      LAYER METAL3 ;
        RECT 4828.05 1633.45 4828.85 1634.25 ;
    END
  END VOUT<1>
  PIN VOUT<276>
    DIRECTION INOUT ;
    USE SIGNAL ;
    PORT
      LAYER METAL3 ;
        RECT 4828.05 118.17 4828.85 118.97 ;
    END
  END VOUT<276>
  PIN VOUT<272>
    DIRECTION INOUT ;
    USE SIGNAL ;
    PORT
      LAYER METAL3 ;
        RECT 4828.05 140.17 4828.85 140.97 ;
    END
  END VOUT<272>
  PIN VOUT<268>
    DIRECTION INOUT ;
    USE SIGNAL ;
    PORT
      LAYER METAL3 ;
        RECT 4828.05 162.17 4828.85 162.97 ;
    END
  END VOUT<268>
  PIN VOUT<264>
    DIRECTION INOUT ;
    USE SIGNAL ;
    PORT
      LAYER METAL3 ;
        RECT 4828.05 184.17 4828.85 184.97 ;
    END
  END VOUT<264>
  PIN VOUT<260>
    DIRECTION INOUT ;
    USE SIGNAL ;
    PORT
      LAYER METAL3 ;
        RECT 4828.05 206.17 4828.85 206.97 ;
    END
  END VOUT<260>
  PIN VOUT<256>
    DIRECTION INOUT ;
    USE SIGNAL ;
    PORT
      LAYER METAL3 ;
        RECT 4828.05 228.17 4828.85 228.97 ;
    END
  END VOUT<256>
  PIN VOUT<252>
    DIRECTION INOUT ;
    USE SIGNAL ;
    PORT
      LAYER METAL3 ;
        RECT 4828.05 250.17 4828.85 250.97 ;
    END
  END VOUT<252>
  PIN VOUT<248>
    DIRECTION INOUT ;
    USE SIGNAL ;
    PORT
      LAYER METAL3 ;
        RECT 4828.05 272.17 4828.85 272.97 ;
    END
  END VOUT<248>
  PIN VOUT<244>
    DIRECTION INOUT ;
    USE SIGNAL ;
    PORT
      LAYER METAL3 ;
        RECT 4828.05 294.17 4828.85 294.97 ;
    END
  END VOUT<244>
  PIN VOUT<240>
    DIRECTION INOUT ;
    USE SIGNAL ;
    PORT
      LAYER METAL3 ;
        RECT 4828.05 316.17 4828.85 316.97 ;
    END
  END VOUT<240>
  PIN VOUT<236>
    DIRECTION INOUT ;
    USE SIGNAL ;
    PORT
      LAYER METAL3 ;
        RECT 4828.05 338.17 4828.85 338.97 ;
    END
  END VOUT<236>
  PIN VOUT<232>
    DIRECTION INOUT ;
    USE SIGNAL ;
    PORT
      LAYER METAL3 ;
        RECT 4828.05 360.17 4828.85 360.97 ;
    END
  END VOUT<232>
  PIN VOUT<228>
    DIRECTION INOUT ;
    USE SIGNAL ;
    PORT
      LAYER METAL3 ;
        RECT 4828.05 382.17 4828.85 382.97 ;
    END
  END VOUT<228>
  PIN VOUT<224>
    DIRECTION INOUT ;
    USE SIGNAL ;
    PORT
      LAYER METAL3 ;
        RECT 4828.05 404.17 4828.85 404.97 ;
    END
  END VOUT<224>
  PIN VOUT<220>
    DIRECTION INOUT ;
    USE SIGNAL ;
    PORT
      LAYER METAL3 ;
        RECT 4828.05 426.17 4828.85 426.97 ;
    END
  END VOUT<220>
  PIN VOUT<216>
    DIRECTION INOUT ;
    USE SIGNAL ;
    PORT
      LAYER METAL3 ;
        RECT 4828.05 448.17 4828.85 448.97 ;
    END
  END VOUT<216>
  PIN VOUT<212>
    DIRECTION INOUT ;
    USE SIGNAL ;
    PORT
      LAYER METAL3 ;
        RECT 4828.05 470.17 4828.85 470.97 ;
    END
  END VOUT<212>
  PIN VOUT<208>
    DIRECTION INOUT ;
    USE SIGNAL ;
    PORT
      LAYER METAL3 ;
        RECT 4828.05 492.17 4828.85 492.97 ;
    END
  END VOUT<208>
  PIN VOUT<204>
    DIRECTION INOUT ;
    USE SIGNAL ;
    PORT
      LAYER METAL3 ;
        RECT 4828.05 514.17 4828.85 514.97 ;
    END
  END VOUT<204>
  PIN VOUT<200>
    DIRECTION INOUT ;
    USE SIGNAL ;
    PORT
      LAYER METAL3 ;
        RECT 4828.05 536.17 4828.85 536.97 ;
    END
  END VOUT<200>
  PIN VOUT<196>
    DIRECTION INOUT ;
    USE SIGNAL ;
    PORT
      LAYER METAL3 ;
        RECT 4828.05 558.17 4828.85 558.97 ;
    END
  END VOUT<196>
  PIN VOUT<192>
    DIRECTION INOUT ;
    USE SIGNAL ;
    PORT
      LAYER METAL3 ;
        RECT 4828.05 580.17 4828.85 580.97 ;
    END
  END VOUT<192>
  PIN VOUT<188>
    DIRECTION INOUT ;
    USE SIGNAL ;
    PORT
      LAYER METAL3 ;
        RECT 4828.05 602.17 4828.85 602.97 ;
    END
  END VOUT<188>
  PIN VOUT<184>
    DIRECTION INOUT ;
    USE SIGNAL ;
    PORT
      LAYER METAL3 ;
        RECT 4828.05 624.17 4828.85 624.97 ;
    END
  END VOUT<184>
  PIN VOUT<180>
    DIRECTION INOUT ;
    USE SIGNAL ;
    PORT
      LAYER METAL3 ;
        RECT 4828.05 646.17 4828.85 646.97 ;
    END
  END VOUT<180>
  PIN VOUT<176>
    DIRECTION INOUT ;
    USE SIGNAL ;
    PORT
      LAYER METAL3 ;
        RECT 4828.05 668.17 4828.85 668.97 ;
    END
  END VOUT<176>
  PIN VOUT<172>
    DIRECTION INOUT ;
    USE SIGNAL ;
    PORT
      LAYER METAL3 ;
        RECT 4828.05 690.17 4828.85 690.97 ;
    END
  END VOUT<172>
  PIN VOUT<168>
    DIRECTION INOUT ;
    USE SIGNAL ;
    PORT
      LAYER METAL3 ;
        RECT 4828.05 712.17 4828.85 712.97 ;
    END
  END VOUT<168>
  PIN VOUT<164>
    DIRECTION INOUT ;
    USE SIGNAL ;
    PORT
      LAYER METAL3 ;
        RECT 4828.05 734.17 4828.85 734.97 ;
    END
  END VOUT<164>
  PIN VOUT<160>
    DIRECTION INOUT ;
    USE SIGNAL ;
    PORT
      LAYER METAL3 ;
        RECT 4828.05 756.17 4828.85 756.97 ;
    END
  END VOUT<160>
  PIN VOUT<156>
    DIRECTION INOUT ;
    USE SIGNAL ;
    PORT
      LAYER METAL3 ;
        RECT 4828.05 778.17 4828.85 778.97 ;
    END
  END VOUT<156>
  PIN VOUT<152>
    DIRECTION INOUT ;
    USE SIGNAL ;
    PORT
      LAYER METAL3 ;
        RECT 4828.05 800.17 4828.85 800.97 ;
    END
  END VOUT<152>
  PIN VOUT<148>
    DIRECTION INOUT ;
    USE SIGNAL ;
    PORT
      LAYER METAL3 ;
        RECT 4828.05 822.17 4828.85 822.97 ;
    END
  END VOUT<148>
  PIN VOUT<144>
    DIRECTION INOUT ;
    USE SIGNAL ;
    PORT
      LAYER METAL3 ;
        RECT 4828.05 844.17 4828.85 844.97 ;
    END
  END VOUT<144>
  PIN VOUT<140>
    DIRECTION INOUT ;
    USE SIGNAL ;
    PORT
      LAYER METAL3 ;
        RECT 4828.05 866.17 4828.85 866.97 ;
    END
  END VOUT<140>
  PIN VOUT<136>
    DIRECTION INOUT ;
    USE SIGNAL ;
    PORT
      LAYER METAL3 ;
        RECT 4828.05 888.17 4828.85 888.97 ;
    END
  END VOUT<136>
  PIN VOUT<132>
    DIRECTION INOUT ;
    USE SIGNAL ;
    PORT
      LAYER METAL3 ;
        RECT 4828.05 910.17 4828.85 910.97 ;
    END
  END VOUT<132>
  PIN VOUT<128>
    DIRECTION INOUT ;
    USE SIGNAL ;
    PORT
      LAYER METAL3 ;
        RECT 4828.05 932.17 4828.85 932.97 ;
    END
  END VOUT<128>
  PIN VOUT<124>
    DIRECTION INOUT ;
    USE SIGNAL ;
    PORT
      LAYER METAL3 ;
        RECT 4828.05 954.17 4828.85 954.97 ;
    END
  END VOUT<124>
  PIN VOUT<120>
    DIRECTION INOUT ;
    USE SIGNAL ;
    PORT
      LAYER METAL3 ;
        RECT 4828.05 976.17 4828.85 976.97 ;
    END
  END VOUT<120>
  PIN VOUT<116>
    DIRECTION INOUT ;
    USE SIGNAL ;
    PORT
      LAYER METAL3 ;
        RECT 4828.05 998.17 4828.85 998.97 ;
    END
  END VOUT<116>
  PIN VOUT<112>
    DIRECTION INOUT ;
    USE SIGNAL ;
    PORT
      LAYER METAL3 ;
        RECT 4828.05 1020.17 4828.85 1020.97 ;
    END
  END VOUT<112>
  PIN VOUT<108>
    DIRECTION INOUT ;
    USE SIGNAL ;
    PORT
      LAYER METAL3 ;
        RECT 4828.05 1042.17 4828.85 1042.97 ;
    END
  END VOUT<108>
  PIN VOUT<104>
    DIRECTION INOUT ;
    USE SIGNAL ;
    PORT
      LAYER METAL3 ;
        RECT 4828.05 1064.17 4828.85 1064.97 ;
    END
  END VOUT<104>
  PIN VOUT<100>
    DIRECTION INOUT ;
    USE SIGNAL ;
    PORT
      LAYER METAL3 ;
        RECT 4828.05 1086.17 4828.85 1086.97 ;
    END
  END VOUT<100>
  PIN VOUT<96>
    DIRECTION INOUT ;
    USE SIGNAL ;
    PORT
      LAYER METAL3 ;
        RECT 4828.05 1108.17 4828.85 1108.97 ;
    END
  END VOUT<96>
  PIN VOUT<92>
    DIRECTION INOUT ;
    USE SIGNAL ;
    PORT
      LAYER METAL3 ;
        RECT 4828.05 1130.17 4828.85 1130.97 ;
    END
  END VOUT<92>
  PIN VOUT<88>
    DIRECTION INOUT ;
    USE SIGNAL ;
    PORT
      LAYER METAL3 ;
        RECT 4828.05 1152.17 4828.85 1152.97 ;
    END
  END VOUT<88>
  PIN VOUT<84>
    DIRECTION INOUT ;
    USE SIGNAL ;
    PORT
      LAYER METAL3 ;
        RECT 4828.05 1174.17 4828.85 1174.97 ;
    END
  END VOUT<84>
  PIN VOUT<80>
    DIRECTION INOUT ;
    USE SIGNAL ;
    PORT
      LAYER METAL3 ;
        RECT 4828.05 1196.17 4828.85 1196.97 ;
    END
  END VOUT<80>
  PIN VOUT<76>
    DIRECTION INOUT ;
    USE SIGNAL ;
    PORT
      LAYER METAL3 ;
        RECT 4828.05 1218.17 4828.85 1218.97 ;
    END
  END VOUT<76>
  PIN VOUT<72>
    DIRECTION INOUT ;
    USE SIGNAL ;
    PORT
      LAYER METAL3 ;
        RECT 4828.05 1240.17 4828.85 1240.97 ;
    END
  END VOUT<72>
  PIN VOUT<68>
    DIRECTION INOUT ;
    USE SIGNAL ;
    PORT
      LAYER METAL3 ;
        RECT 4828.05 1262.17 4828.85 1262.97 ;
    END
  END VOUT<68>
  PIN VOUT<64>
    DIRECTION INOUT ;
    USE SIGNAL ;
    PORT
      LAYER METAL3 ;
        RECT 4828.05 1284.17 4828.85 1284.97 ;
    END
  END VOUT<64>
  PIN VOUT<60>
    DIRECTION INOUT ;
    USE SIGNAL ;
    PORT
      LAYER METAL3 ;
        RECT 4828.05 1306.17 4828.85 1306.97 ;
    END
  END VOUT<60>
  PIN VOUT<56>
    DIRECTION INOUT ;
    USE SIGNAL ;
    PORT
      LAYER METAL3 ;
        RECT 4828.05 1328.17 4828.85 1328.97 ;
    END
  END VOUT<56>
  PIN VOUT<52>
    DIRECTION INOUT ;
    USE SIGNAL ;
    PORT
      LAYER METAL3 ;
        RECT 4828.05 1350.17 4828.85 1350.97 ;
    END
  END VOUT<52>
  PIN VOUT<48>
    DIRECTION INOUT ;
    USE SIGNAL ;
    PORT
      LAYER METAL3 ;
        RECT 4828.05 1372.17 4828.85 1372.97 ;
    END
  END VOUT<48>
  PIN VOUT<44>
    DIRECTION INOUT ;
    USE SIGNAL ;
    PORT
      LAYER METAL3 ;
        RECT 4828.05 1394.17 4828.85 1394.97 ;
    END
  END VOUT<44>
  PIN VOUT<40>
    DIRECTION INOUT ;
    USE SIGNAL ;
    PORT
      LAYER METAL3 ;
        RECT 4828.05 1416.17 4828.85 1416.97 ;
    END
  END VOUT<40>
  PIN VOUT<36>
    DIRECTION INOUT ;
    USE SIGNAL ;
    PORT
      LAYER METAL3 ;
        RECT 4828.05 1438.17 4828.85 1438.97 ;
    END
  END VOUT<36>
  PIN VOUT<32>
    DIRECTION INOUT ;
    USE SIGNAL ;
    PORT
      LAYER METAL3 ;
        RECT 4828.05 1460.17 4828.85 1460.97 ;
    END
  END VOUT<32>
  PIN VOUT<28>
    DIRECTION INOUT ;
    USE SIGNAL ;
    PORT
      LAYER METAL3 ;
        RECT 4828.05 1482.17 4828.85 1482.97 ;
    END
  END VOUT<28>
  PIN VOUT<24>
    DIRECTION INOUT ;
    USE SIGNAL ;
    PORT
      LAYER METAL3 ;
        RECT 4828.05 1504.17 4828.85 1504.97 ;
    END
  END VOUT<24>
  PIN VOUT<20>
    DIRECTION INOUT ;
    USE SIGNAL ;
    PORT
      LAYER METAL3 ;
        RECT 4828.05 1526.17 4828.85 1526.97 ;
    END
  END VOUT<20>
  PIN VOUT<16>
    DIRECTION INOUT ;
    USE SIGNAL ;
    PORT
      LAYER METAL3 ;
        RECT 4828.05 1548.17 4828.85 1548.97 ;
    END
  END VOUT<16>
  PIN VOUT<12>
    DIRECTION INOUT ;
    USE SIGNAL ;
    PORT
      LAYER METAL3 ;
        RECT 4828.05 1570.17 4828.85 1570.97 ;
    END
  END VOUT<12>
  PIN VOUT<8>
    DIRECTION INOUT ;
    USE SIGNAL ;
    PORT
      LAYER METAL3 ;
        RECT 4828.05 1592.17 4828.85 1592.97 ;
    END
  END VOUT<8>
  PIN VOUT<4>
    DIRECTION INOUT ;
    USE SIGNAL ;
    PORT
      LAYER METAL3 ;
        RECT 4828.05 1614.17 4828.85 1614.97 ;
    END
  END VOUT<4>
  PIN VOUT<0>
    DIRECTION INOUT ;
    USE SIGNAL ;
    PORT
      LAYER METAL3 ;
        RECT 4828.05 1636.17 4828.85 1636.97 ;
    END
  END VOUT<0>
  PIN w_DrainEnable_Mod
    DIRECTION INOUT ;
    USE SIGNAL ;
    PORT
      LAYER METAL3 ;
        RECT 0.0 1750.57 2.8 1751.97 ;
    END
  END w_DrainEnable_Mod
  PIN w_Drainline_Run
    DIRECTION INOUT ;
    USE SIGNAL ;
    PORT
      LAYER METAL3 ;
        RECT 0.0 1764.57 2.8 1765.97 ;
    END
  END w_Drainline_Run
  PIN w_Drainline_Prog
    DIRECTION INOUT ;
    USE SIGNAL ;
    PORT
      LAYER METAL3 ;
        RECT 0.0 1778.57 2.8 1779.97 ;
    END
  END w_Drainline_Prog
  PIN w_DrainB<8>
    DIRECTION INOUT ;
    USE SIGNAL ;
    PORT
      LAYER METAL3 ;
        RECT 0.0 1792.57 2.8 1793.97 ;
    END
  END w_DrainB<8>
  PIN w_DrainB<7>
    DIRECTION INOUT ;
    USE SIGNAL ;
    PORT
      LAYER METAL3 ;
        RECT 0.0 1806.57 2.8 1807.97 ;
    END
  END w_DrainB<7>
  PIN w_DrainB<6>
    DIRECTION INOUT ;
    USE SIGNAL ;
    PORT
      LAYER METAL3 ;
        RECT 0.0 1820.57 2.8 1821.97 ;
    END
  END w_DrainB<6>
  PIN w_DrainB<5>
    DIRECTION INOUT ;
    USE SIGNAL ;
    PORT
      LAYER METAL3 ;
        RECT 0.0 1834.57 2.8 1835.97 ;
    END
  END w_DrainB<5>
  PIN w_DrainB<4>
    DIRECTION INOUT ;
    USE SIGNAL ;
    PORT
      LAYER METAL3 ;
        RECT 0.0 1848.57 2.8 1849.97 ;
    END
  END w_DrainB<4>
  PIN w_DrainB<3>
    DIRECTION INOUT ;
    USE SIGNAL ;
    PORT
      LAYER METAL3 ;
        RECT 0.0 1862.57 2.8 1863.97 ;
    END
  END w_DrainB<3>
  PIN w_DrainB<2>
    DIRECTION INOUT ;
    USE SIGNAL ;
    PORT
      LAYER METAL3 ;
        RECT 0.0 1876.57 2.8 1877.97 ;
    END
  END w_DrainB<2>
  PIN w_DrainB<1>
    DIRECTION INOUT ;
    USE SIGNAL ;
    PORT
      LAYER METAL3 ;
        RECT 0.0 1890.57 2.8 1891.97 ;
    END
  END w_DrainB<1>
  PIN w_DrainB<0>
    DIRECTION INOUT ;
    USE SIGNAL ;
    PORT
      LAYER METAL3 ;
        RECT 0.0 1904.57 2.8 1905.97 ;
    END
  END w_DrainB<0>
  PIN s_vinj
    DIRECTION INOUT ;
    USE SIGNAL ;
    PORT
      LAYER METAL3 ;
        RECT 4984.6 0.0 4986.0 2.8 ;
    END
  END s_vinj
  PIN s_gnd
    DIRECTION INOUT ;
    USE SIGNAL ;
    PORT
      LAYER METAL3 ;
        RECT 4998.6 0.0 5000.0 2.8 ;
    END
  END s_gnd
  PIN n_VC
    DIRECTION INOUT ;
    USE SIGNAL ;
    PORT
      LAYER METAL3 ;
        RECT 251.3 1917.17 252.7 1919.97 ;
    END
  END n_VC
  PIN n_VG_P
    DIRECTION INOUT ;
    USE SIGNAL ;
    PORT
      LAYER METAL3 ;
        RECT 237.3 1917.17 238.7 1919.97 ;
    END
  END n_VG_P
  PIN n_VG_N
    DIRECTION INOUT ;
    USE SIGNAL ;
    PORT
      LAYER METAL3 ;
        RECT 223.3 1917.17 224.7 1919.97 ;
    END
  END n_VG_N
  PIN n_GateEnable_Mod
    DIRECTION INOUT ;
    USE SIGNAL ;
    PORT
      LAYER METAL3 ;
        RECT 209.3 1917.17 210.7 1919.97 ;
    END
  END n_GateEnable_Mod
  PIN n_GateB<8>
    DIRECTION INOUT ;
    USE SIGNAL ;
    PORT
      LAYER METAL3 ;
        RECT 195.3 1917.17 196.7 1919.97 ;
    END
  END n_GateB<8>
  PIN n_GateB<7>
    DIRECTION INOUT ;
    USE SIGNAL ;
    PORT
      LAYER METAL3 ;
        RECT 181.3 1917.17 182.7 1919.97 ;
    END
  END n_GateB<7>
  PIN n_GateB<6>
    DIRECTION INOUT ;
    USE SIGNAL ;
    PORT
      LAYER METAL3 ;
        RECT 167.3 1917.17 168.7 1919.97 ;
    END
  END n_GateB<6>
  PIN n_GateB<5>
    DIRECTION INOUT ;
    USE SIGNAL ;
    PORT
      LAYER METAL3 ;
        RECT 153.3 1917.17 154.7 1919.97 ;
    END
  END n_GateB<5>
  PIN n_GateB<4>
    DIRECTION INOUT ;
    USE SIGNAL ;
    PORT
      LAYER METAL3 ;
        RECT 139.3 1917.17 140.7 1919.97 ;
    END
  END n_GateB<4>
  PIN n_GateB<3>
    DIRECTION INOUT ;
    USE SIGNAL ;
    PORT
      LAYER METAL3 ;
        RECT 125.3 1917.17 126.7 1919.97 ;
    END
  END n_GateB<3>
  PIN n_GateB<2>
    DIRECTION INOUT ;
    USE SIGNAL ;
    PORT
      LAYER METAL3 ;
        RECT 111.3 1917.17 112.7 1919.97 ;
    END
  END n_GateB<2>
  PIN n_GateB<1>
    DIRECTION INOUT ;
    USE SIGNAL ;
    PORT
      LAYER METAL3 ;
        RECT 97.3 1917.17 98.7 1919.97 ;
    END
  END n_GateB<1>
  PIN n_GateB<0>
    DIRECTION INOUT ;
    USE SIGNAL ;
    PORT
      LAYER METAL3 ;
        RECT 83.3 1917.17 84.7 1919.97 ;
    END
  END n_GateB<0>
  PIN n_vinj
    DIRECTION INOUT ;
    USE SIGNAL ;
    PORT
      LAYER METAL3 ;
        RECT 4984.6 1917.17 4986.0 1919.97 ;
    END
  END n_vinj
  PIN n_gnd
    DIRECTION INOUT ;
    USE SIGNAL ;
    PORT
      LAYER METAL3 ;
        RECT 4998.6 1917.17 5000.0 1919.97 ;
    END
  END n_gnd
  PIN n_AVDD
    DIRECTION INOUT ;
    USE SIGNAL ;
    PORT
      LAYER METAL3 ;
        RECT 69.3 1917.17 70.7 1919.97 ;
    END
  END n_AVDD
  PIN n_VTUN
    DIRECTION INOUT ;
    USE SIGNAL ;
    PORT
      LAYER METAL3 ;
        RECT 55.3 1917.17 56.7 1919.97 ;
    END
  END n_VTUN
  PIN n_VGPROG
    DIRECTION INOUT ;
    USE SIGNAL ;
    PORT
      LAYER METAL3 ;
        RECT 41.3 1917.17 42.7 1919.97 ;
    END
  END n_VGPROG
  PIN n_Run
    DIRECTION INOUT ;
    USE SIGNAL ;
    PORT
      LAYER METAL3 ;
        RECT 27.3 1917.17 28.7 1919.97 ;
    END
  END n_Run
  PIN n_Prog
    DIRECTION INOUT ;
    USE SIGNAL ;
    PORT
      LAYER METAL3 ;
        RECT 13.3 1917.17 14.7 1919.97 ;
    END
  END n_Prog
END Modulation

MACRO VMMWTA
  PIN VGRUN<279>
    DIRECTION INOUT ;
    USE SIGNAL ;
    PORT
      LAYER METAL3 ;
        RECT 4064.37 1687.57 4065.17 1688.37 ;
    END
  END VGRUN<279>
  PIN VGRUN<275>
    DIRECTION INOUT ;
    USE SIGNAL ;
    PORT
      LAYER METAL3 ;
        RECT 4009.45 1687.57 4010.25 1688.37 ;
    END
  END VGRUN<275>
  PIN VGRUN<271>
    DIRECTION INOUT ;
    USE SIGNAL ;
    PORT
      LAYER METAL3 ;
        RECT 3954.53 1687.57 3955.33 1688.37 ;
    END
  END VGRUN<271>
  PIN VGRUN<267>
    DIRECTION INOUT ;
    USE SIGNAL ;
    PORT
      LAYER METAL3 ;
        RECT 3899.61 1687.57 3900.41 1688.37 ;
    END
  END VGRUN<267>
  PIN VGRUN<263>
    DIRECTION INOUT ;
    USE SIGNAL ;
    PORT
      LAYER METAL3 ;
        RECT 3844.69 1687.57 3845.49 1688.37 ;
    END
  END VGRUN<263>
  PIN VGRUN<259>
    DIRECTION INOUT ;
    USE SIGNAL ;
    PORT
      LAYER METAL3 ;
        RECT 3789.77 1687.57 3790.57 1688.37 ;
    END
  END VGRUN<259>
  PIN VGRUN<255>
    DIRECTION INOUT ;
    USE SIGNAL ;
    PORT
      LAYER METAL3 ;
        RECT 3734.85 1687.57 3735.65 1688.37 ;
    END
  END VGRUN<255>
  PIN VGRUN<251>
    DIRECTION INOUT ;
    USE SIGNAL ;
    PORT
      LAYER METAL3 ;
        RECT 3679.93 1687.57 3680.73 1688.37 ;
    END
  END VGRUN<251>
  PIN VGRUN<247>
    DIRECTION INOUT ;
    USE SIGNAL ;
    PORT
      LAYER METAL3 ;
        RECT 3625.01 1687.57 3625.81 1688.37 ;
    END
  END VGRUN<247>
  PIN VGRUN<243>
    DIRECTION INOUT ;
    USE SIGNAL ;
    PORT
      LAYER METAL3 ;
        RECT 3570.09 1687.57 3570.89 1688.37 ;
    END
  END VGRUN<243>
  PIN VGRUN<239>
    DIRECTION INOUT ;
    USE SIGNAL ;
    PORT
      LAYER METAL3 ;
        RECT 3515.17 1687.57 3515.97 1688.37 ;
    END
  END VGRUN<239>
  PIN VGRUN<235>
    DIRECTION INOUT ;
    USE SIGNAL ;
    PORT
      LAYER METAL3 ;
        RECT 3460.25 1687.57 3461.05 1688.37 ;
    END
  END VGRUN<235>
  PIN VGRUN<231>
    DIRECTION INOUT ;
    USE SIGNAL ;
    PORT
      LAYER METAL3 ;
        RECT 3405.33 1687.57 3406.13 1688.37 ;
    END
  END VGRUN<231>
  PIN VGRUN<227>
    DIRECTION INOUT ;
    USE SIGNAL ;
    PORT
      LAYER METAL3 ;
        RECT 3350.41 1687.57 3351.21 1688.37 ;
    END
  END VGRUN<227>
  PIN VGRUN<223>
    DIRECTION INOUT ;
    USE SIGNAL ;
    PORT
      LAYER METAL3 ;
        RECT 3295.49 1687.57 3296.29 1688.37 ;
    END
  END VGRUN<223>
  PIN VGRUN<219>
    DIRECTION INOUT ;
    USE SIGNAL ;
    PORT
      LAYER METAL3 ;
        RECT 3240.57 1687.57 3241.37 1688.37 ;
    END
  END VGRUN<219>
  PIN VGRUN<215>
    DIRECTION INOUT ;
    USE SIGNAL ;
    PORT
      LAYER METAL3 ;
        RECT 3185.65 1687.57 3186.45 1688.37 ;
    END
  END VGRUN<215>
  PIN VGRUN<211>
    DIRECTION INOUT ;
    USE SIGNAL ;
    PORT
      LAYER METAL3 ;
        RECT 3130.73 1687.57 3131.53 1688.37 ;
    END
  END VGRUN<211>
  PIN VGRUN<207>
    DIRECTION INOUT ;
    USE SIGNAL ;
    PORT
      LAYER METAL3 ;
        RECT 3075.81 1687.57 3076.61 1688.37 ;
    END
  END VGRUN<207>
  PIN VGRUN<203>
    DIRECTION INOUT ;
    USE SIGNAL ;
    PORT
      LAYER METAL3 ;
        RECT 3020.89 1687.57 3021.69 1688.37 ;
    END
  END VGRUN<203>
  PIN VGRUN<199>
    DIRECTION INOUT ;
    USE SIGNAL ;
    PORT
      LAYER METAL3 ;
        RECT 2965.97 1687.57 2966.77 1688.37 ;
    END
  END VGRUN<199>
  PIN VGRUN<195>
    DIRECTION INOUT ;
    USE SIGNAL ;
    PORT
      LAYER METAL3 ;
        RECT 2911.05 1687.57 2911.85 1688.37 ;
    END
  END VGRUN<195>
  PIN VGRUN<191>
    DIRECTION INOUT ;
    USE SIGNAL ;
    PORT
      LAYER METAL3 ;
        RECT 2856.13 1687.57 2856.93 1688.37 ;
    END
  END VGRUN<191>
  PIN VGRUN<187>
    DIRECTION INOUT ;
    USE SIGNAL ;
    PORT
      LAYER METAL3 ;
        RECT 2801.21 1687.57 2802.01 1688.37 ;
    END
  END VGRUN<187>
  PIN VGRUN<183>
    DIRECTION INOUT ;
    USE SIGNAL ;
    PORT
      LAYER METAL3 ;
        RECT 2746.29 1687.57 2747.09 1688.37 ;
    END
  END VGRUN<183>
  PIN VGRUN<179>
    DIRECTION INOUT ;
    USE SIGNAL ;
    PORT
      LAYER METAL3 ;
        RECT 2691.37 1687.57 2692.17 1688.37 ;
    END
  END VGRUN<179>
  PIN VGRUN<175>
    DIRECTION INOUT ;
    USE SIGNAL ;
    PORT
      LAYER METAL3 ;
        RECT 2636.45 1687.57 2637.25 1688.37 ;
    END
  END VGRUN<175>
  PIN VGRUN<171>
    DIRECTION INOUT ;
    USE SIGNAL ;
    PORT
      LAYER METAL3 ;
        RECT 2581.53 1687.57 2582.33 1688.37 ;
    END
  END VGRUN<171>
  PIN VGRUN<167>
    DIRECTION INOUT ;
    USE SIGNAL ;
    PORT
      LAYER METAL3 ;
        RECT 2526.61 1687.57 2527.41 1688.37 ;
    END
  END VGRUN<167>
  PIN VGRUN<163>
    DIRECTION INOUT ;
    USE SIGNAL ;
    PORT
      LAYER METAL3 ;
        RECT 2471.69 1687.57 2472.49 1688.37 ;
    END
  END VGRUN<163>
  PIN VGRUN<159>
    DIRECTION INOUT ;
    USE SIGNAL ;
    PORT
      LAYER METAL3 ;
        RECT 2416.77 1687.57 2417.57 1688.37 ;
    END
  END VGRUN<159>
  PIN VGRUN<155>
    DIRECTION INOUT ;
    USE SIGNAL ;
    PORT
      LAYER METAL3 ;
        RECT 2361.85 1687.57 2362.65 1688.37 ;
    END
  END VGRUN<155>
  PIN VGRUN<151>
    DIRECTION INOUT ;
    USE SIGNAL ;
    PORT
      LAYER METAL3 ;
        RECT 2306.93 1687.57 2307.73 1688.37 ;
    END
  END VGRUN<151>
  PIN VGRUN<147>
    DIRECTION INOUT ;
    USE SIGNAL ;
    PORT
      LAYER METAL3 ;
        RECT 2252.01 1687.57 2252.81 1688.37 ;
    END
  END VGRUN<147>
  PIN VGRUN<143>
    DIRECTION INOUT ;
    USE SIGNAL ;
    PORT
      LAYER METAL3 ;
        RECT 2197.09 1687.57 2197.89 1688.37 ;
    END
  END VGRUN<143>
  PIN VGRUN<139>
    DIRECTION INOUT ;
    USE SIGNAL ;
    PORT
      LAYER METAL3 ;
        RECT 2142.17 1687.57 2142.97 1688.37 ;
    END
  END VGRUN<139>
  PIN VGRUN<135>
    DIRECTION INOUT ;
    USE SIGNAL ;
    PORT
      LAYER METAL3 ;
        RECT 2087.25 1687.57 2088.05 1688.37 ;
    END
  END VGRUN<135>
  PIN VGRUN<131>
    DIRECTION INOUT ;
    USE SIGNAL ;
    PORT
      LAYER METAL3 ;
        RECT 2032.33 1687.57 2033.13 1688.37 ;
    END
  END VGRUN<131>
  PIN VGRUN<127>
    DIRECTION INOUT ;
    USE SIGNAL ;
    PORT
      LAYER METAL3 ;
        RECT 1977.41 1687.57 1978.21 1688.37 ;
    END
  END VGRUN<127>
  PIN VGRUN<123>
    DIRECTION INOUT ;
    USE SIGNAL ;
    PORT
      LAYER METAL3 ;
        RECT 1922.49 1687.57 1923.29 1688.37 ;
    END
  END VGRUN<123>
  PIN VGRUN<119>
    DIRECTION INOUT ;
    USE SIGNAL ;
    PORT
      LAYER METAL3 ;
        RECT 1867.57 1687.57 1868.37 1688.37 ;
    END
  END VGRUN<119>
  PIN VGRUN<115>
    DIRECTION INOUT ;
    USE SIGNAL ;
    PORT
      LAYER METAL3 ;
        RECT 1812.65 1687.57 1813.45 1688.37 ;
    END
  END VGRUN<115>
  PIN VGRUN<111>
    DIRECTION INOUT ;
    USE SIGNAL ;
    PORT
      LAYER METAL3 ;
        RECT 1757.73 1687.57 1758.53 1688.37 ;
    END
  END VGRUN<111>
  PIN VGRUN<107>
    DIRECTION INOUT ;
    USE SIGNAL ;
    PORT
      LAYER METAL3 ;
        RECT 1702.81 1687.57 1703.61 1688.37 ;
    END
  END VGRUN<107>
  PIN VGRUN<103>
    DIRECTION INOUT ;
    USE SIGNAL ;
    PORT
      LAYER METAL3 ;
        RECT 1647.89 1687.57 1648.69 1688.37 ;
    END
  END VGRUN<103>
  PIN VGRUN<99>
    DIRECTION INOUT ;
    USE SIGNAL ;
    PORT
      LAYER METAL3 ;
        RECT 1592.97 1687.57 1593.77 1688.37 ;
    END
  END VGRUN<99>
  PIN VGRUN<95>
    DIRECTION INOUT ;
    USE SIGNAL ;
    PORT
      LAYER METAL3 ;
        RECT 1538.05 1687.57 1538.85 1688.37 ;
    END
  END VGRUN<95>
  PIN VGRUN<91>
    DIRECTION INOUT ;
    USE SIGNAL ;
    PORT
      LAYER METAL3 ;
        RECT 1483.13 1687.57 1483.93 1688.37 ;
    END
  END VGRUN<91>
  PIN VGRUN<87>
    DIRECTION INOUT ;
    USE SIGNAL ;
    PORT
      LAYER METAL3 ;
        RECT 1428.21 1687.57 1429.01 1688.37 ;
    END
  END VGRUN<87>
  PIN VGRUN<83>
    DIRECTION INOUT ;
    USE SIGNAL ;
    PORT
      LAYER METAL3 ;
        RECT 1373.29 1687.57 1374.09 1688.37 ;
    END
  END VGRUN<83>
  PIN VGRUN<79>
    DIRECTION INOUT ;
    USE SIGNAL ;
    PORT
      LAYER METAL3 ;
        RECT 1318.37 1687.57 1319.17 1688.37 ;
    END
  END VGRUN<79>
  PIN VGRUN<75>
    DIRECTION INOUT ;
    USE SIGNAL ;
    PORT
      LAYER METAL3 ;
        RECT 1263.45 1687.57 1264.25 1688.37 ;
    END
  END VGRUN<75>
  PIN VGRUN<71>
    DIRECTION INOUT ;
    USE SIGNAL ;
    PORT
      LAYER METAL3 ;
        RECT 1208.53 1687.57 1209.33 1688.37 ;
    END
  END VGRUN<71>
  PIN VGRUN<67>
    DIRECTION INOUT ;
    USE SIGNAL ;
    PORT
      LAYER METAL3 ;
        RECT 1153.61 1687.57 1154.41 1688.37 ;
    END
  END VGRUN<67>
  PIN VGRUN<63>
    DIRECTION INOUT ;
    USE SIGNAL ;
    PORT
      LAYER METAL3 ;
        RECT 1098.69 1687.57 1099.49 1688.37 ;
    END
  END VGRUN<63>
  PIN VGRUN<59>
    DIRECTION INOUT ;
    USE SIGNAL ;
    PORT
      LAYER METAL3 ;
        RECT 1043.77 1687.57 1044.57 1688.37 ;
    END
  END VGRUN<59>
  PIN VGRUN<55>
    DIRECTION INOUT ;
    USE SIGNAL ;
    PORT
      LAYER METAL3 ;
        RECT 988.85 1687.57 989.65 1688.37 ;
    END
  END VGRUN<55>
  PIN VGRUN<51>
    DIRECTION INOUT ;
    USE SIGNAL ;
    PORT
      LAYER METAL3 ;
        RECT 933.93 1687.57 934.73 1688.37 ;
    END
  END VGRUN<51>
  PIN VGRUN<47>
    DIRECTION INOUT ;
    USE SIGNAL ;
    PORT
      LAYER METAL3 ;
        RECT 879.01 1687.57 879.81 1688.37 ;
    END
  END VGRUN<47>
  PIN VGRUN<43>
    DIRECTION INOUT ;
    USE SIGNAL ;
    PORT
      LAYER METAL3 ;
        RECT 824.09 1687.57 824.89 1688.37 ;
    END
  END VGRUN<43>
  PIN VGRUN<39>
    DIRECTION INOUT ;
    USE SIGNAL ;
    PORT
      LAYER METAL3 ;
        RECT 769.17 1687.57 769.97 1688.37 ;
    END
  END VGRUN<39>
  PIN VGRUN<35>
    DIRECTION INOUT ;
    USE SIGNAL ;
    PORT
      LAYER METAL3 ;
        RECT 714.25 1687.57 715.05 1688.37 ;
    END
  END VGRUN<35>
  PIN VGRUN<31>
    DIRECTION INOUT ;
    USE SIGNAL ;
    PORT
      LAYER METAL3 ;
        RECT 659.33 1687.57 660.13 1688.37 ;
    END
  END VGRUN<31>
  PIN VGRUN<27>
    DIRECTION INOUT ;
    USE SIGNAL ;
    PORT
      LAYER METAL3 ;
        RECT 604.41 1687.57 605.21 1688.37 ;
    END
  END VGRUN<27>
  PIN VGRUN<23>
    DIRECTION INOUT ;
    USE SIGNAL ;
    PORT
      LAYER METAL3 ;
        RECT 549.49 1687.57 550.29 1688.37 ;
    END
  END VGRUN<23>
  PIN VGRUN<19>
    DIRECTION INOUT ;
    USE SIGNAL ;
    PORT
      LAYER METAL3 ;
        RECT 494.57 1687.57 495.37 1688.37 ;
    END
  END VGRUN<19>
  PIN VGRUN<15>
    DIRECTION INOUT ;
    USE SIGNAL ;
    PORT
      LAYER METAL3 ;
        RECT 439.65 1687.57 440.45 1688.37 ;
    END
  END VGRUN<15>
  PIN VGRUN<11>
    DIRECTION INOUT ;
    USE SIGNAL ;
    PORT
      LAYER METAL3 ;
        RECT 384.73 1687.57 385.53 1688.37 ;
    END
  END VGRUN<11>
  PIN VGRUN<7>
    DIRECTION INOUT ;
    USE SIGNAL ;
    PORT
      LAYER METAL3 ;
        RECT 329.81 1687.57 330.61 1688.37 ;
    END
  END VGRUN<7>
  PIN VGRUN<3>
    DIRECTION INOUT ;
    USE SIGNAL ;
    PORT
      LAYER METAL3 ;
        RECT 274.89 1687.57 275.69 1688.37 ;
    END
  END VGRUN<3>
  PIN VGRUN<278>
    DIRECTION INOUT ;
    USE SIGNAL ;
    PORT
      LAYER METAL3 ;
        RECT 4059.47 1687.57 4060.27 1688.37 ;
    END
  END VGRUN<278>
  PIN VGRUN<274>
    DIRECTION INOUT ;
    USE SIGNAL ;
    PORT
      LAYER METAL3 ;
        RECT 4004.55 1687.57 4005.35 1688.37 ;
    END
  END VGRUN<274>
  PIN VGRUN<270>
    DIRECTION INOUT ;
    USE SIGNAL ;
    PORT
      LAYER METAL3 ;
        RECT 3949.63 1687.57 3950.43 1688.37 ;
    END
  END VGRUN<270>
  PIN VGRUN<266>
    DIRECTION INOUT ;
    USE SIGNAL ;
    PORT
      LAYER METAL3 ;
        RECT 3894.71 1687.57 3895.51 1688.37 ;
    END
  END VGRUN<266>
  PIN VGRUN<262>
    DIRECTION INOUT ;
    USE SIGNAL ;
    PORT
      LAYER METAL3 ;
        RECT 3839.79 1687.57 3840.59 1688.37 ;
    END
  END VGRUN<262>
  PIN VGRUN<258>
    DIRECTION INOUT ;
    USE SIGNAL ;
    PORT
      LAYER METAL3 ;
        RECT 3784.87 1687.57 3785.67 1688.37 ;
    END
  END VGRUN<258>
  PIN VGRUN<254>
    DIRECTION INOUT ;
    USE SIGNAL ;
    PORT
      LAYER METAL3 ;
        RECT 3729.95 1687.57 3730.75 1688.37 ;
    END
  END VGRUN<254>
  PIN VGRUN<250>
    DIRECTION INOUT ;
    USE SIGNAL ;
    PORT
      LAYER METAL3 ;
        RECT 3675.03 1687.57 3675.83 1688.37 ;
    END
  END VGRUN<250>
  PIN VGRUN<246>
    DIRECTION INOUT ;
    USE SIGNAL ;
    PORT
      LAYER METAL3 ;
        RECT 3620.11 1687.57 3620.91 1688.37 ;
    END
  END VGRUN<246>
  PIN VGRUN<242>
    DIRECTION INOUT ;
    USE SIGNAL ;
    PORT
      LAYER METAL3 ;
        RECT 3565.19 1687.57 3565.99 1688.37 ;
    END
  END VGRUN<242>
  PIN VGRUN<238>
    DIRECTION INOUT ;
    USE SIGNAL ;
    PORT
      LAYER METAL3 ;
        RECT 3510.27 1687.57 3511.07 1688.37 ;
    END
  END VGRUN<238>
  PIN VGRUN<234>
    DIRECTION INOUT ;
    USE SIGNAL ;
    PORT
      LAYER METAL3 ;
        RECT 3455.35 1687.57 3456.15 1688.37 ;
    END
  END VGRUN<234>
  PIN VGRUN<230>
    DIRECTION INOUT ;
    USE SIGNAL ;
    PORT
      LAYER METAL3 ;
        RECT 3400.43 1687.57 3401.23 1688.37 ;
    END
  END VGRUN<230>
  PIN VGRUN<226>
    DIRECTION INOUT ;
    USE SIGNAL ;
    PORT
      LAYER METAL3 ;
        RECT 3345.51 1687.57 3346.31 1688.37 ;
    END
  END VGRUN<226>
  PIN VGRUN<222>
    DIRECTION INOUT ;
    USE SIGNAL ;
    PORT
      LAYER METAL3 ;
        RECT 3290.59 1687.57 3291.39 1688.37 ;
    END
  END VGRUN<222>
  PIN VGRUN<218>
    DIRECTION INOUT ;
    USE SIGNAL ;
    PORT
      LAYER METAL3 ;
        RECT 3235.67 1687.57 3236.47 1688.37 ;
    END
  END VGRUN<218>
  PIN VGRUN<214>
    DIRECTION INOUT ;
    USE SIGNAL ;
    PORT
      LAYER METAL3 ;
        RECT 3180.75 1687.57 3181.55 1688.37 ;
    END
  END VGRUN<214>
  PIN VGRUN<210>
    DIRECTION INOUT ;
    USE SIGNAL ;
    PORT
      LAYER METAL3 ;
        RECT 3125.83 1687.57 3126.63 1688.37 ;
    END
  END VGRUN<210>
  PIN VGRUN<206>
    DIRECTION INOUT ;
    USE SIGNAL ;
    PORT
      LAYER METAL3 ;
        RECT 3070.91 1687.57 3071.71 1688.37 ;
    END
  END VGRUN<206>
  PIN VGRUN<202>
    DIRECTION INOUT ;
    USE SIGNAL ;
    PORT
      LAYER METAL3 ;
        RECT 3015.99 1687.57 3016.79 1688.37 ;
    END
  END VGRUN<202>
  PIN VGRUN<198>
    DIRECTION INOUT ;
    USE SIGNAL ;
    PORT
      LAYER METAL3 ;
        RECT 2961.07 1687.57 2961.87 1688.37 ;
    END
  END VGRUN<198>
  PIN VGRUN<194>
    DIRECTION INOUT ;
    USE SIGNAL ;
    PORT
      LAYER METAL3 ;
        RECT 2906.15 1687.57 2906.95 1688.37 ;
    END
  END VGRUN<194>
  PIN VGRUN<190>
    DIRECTION INOUT ;
    USE SIGNAL ;
    PORT
      LAYER METAL3 ;
        RECT 2851.23 1687.57 2852.03 1688.37 ;
    END
  END VGRUN<190>
  PIN VGRUN<186>
    DIRECTION INOUT ;
    USE SIGNAL ;
    PORT
      LAYER METAL3 ;
        RECT 2796.31 1687.57 2797.11 1688.37 ;
    END
  END VGRUN<186>
  PIN VGRUN<182>
    DIRECTION INOUT ;
    USE SIGNAL ;
    PORT
      LAYER METAL3 ;
        RECT 2741.39 1687.57 2742.19 1688.37 ;
    END
  END VGRUN<182>
  PIN VGRUN<178>
    DIRECTION INOUT ;
    USE SIGNAL ;
    PORT
      LAYER METAL3 ;
        RECT 2686.47 1687.57 2687.27 1688.37 ;
    END
  END VGRUN<178>
  PIN VGRUN<174>
    DIRECTION INOUT ;
    USE SIGNAL ;
    PORT
      LAYER METAL3 ;
        RECT 2631.55 1687.57 2632.35 1688.37 ;
    END
  END VGRUN<174>
  PIN VGRUN<170>
    DIRECTION INOUT ;
    USE SIGNAL ;
    PORT
      LAYER METAL3 ;
        RECT 2576.63 1687.57 2577.43 1688.37 ;
    END
  END VGRUN<170>
  PIN VGRUN<166>
    DIRECTION INOUT ;
    USE SIGNAL ;
    PORT
      LAYER METAL3 ;
        RECT 2521.71 1687.57 2522.51 1688.37 ;
    END
  END VGRUN<166>
  PIN VGRUN<162>
    DIRECTION INOUT ;
    USE SIGNAL ;
    PORT
      LAYER METAL3 ;
        RECT 2466.79 1687.57 2467.59 1688.37 ;
    END
  END VGRUN<162>
  PIN VGRUN<158>
    DIRECTION INOUT ;
    USE SIGNAL ;
    PORT
      LAYER METAL3 ;
        RECT 2411.87 1687.57 2412.67 1688.37 ;
    END
  END VGRUN<158>
  PIN VGRUN<154>
    DIRECTION INOUT ;
    USE SIGNAL ;
    PORT
      LAYER METAL3 ;
        RECT 2356.95 1687.57 2357.75 1688.37 ;
    END
  END VGRUN<154>
  PIN VGRUN<150>
    DIRECTION INOUT ;
    USE SIGNAL ;
    PORT
      LAYER METAL3 ;
        RECT 2302.03 1687.57 2302.83 1688.37 ;
    END
  END VGRUN<150>
  PIN VGRUN<146>
    DIRECTION INOUT ;
    USE SIGNAL ;
    PORT
      LAYER METAL3 ;
        RECT 2247.11 1687.57 2247.91 1688.37 ;
    END
  END VGRUN<146>
  PIN VGRUN<142>
    DIRECTION INOUT ;
    USE SIGNAL ;
    PORT
      LAYER METAL3 ;
        RECT 2192.19 1687.57 2192.99 1688.37 ;
    END
  END VGRUN<142>
  PIN VGRUN<138>
    DIRECTION INOUT ;
    USE SIGNAL ;
    PORT
      LAYER METAL3 ;
        RECT 2137.27 1687.57 2138.07 1688.37 ;
    END
  END VGRUN<138>
  PIN VGRUN<134>
    DIRECTION INOUT ;
    USE SIGNAL ;
    PORT
      LAYER METAL3 ;
        RECT 2082.35 1687.57 2083.15 1688.37 ;
    END
  END VGRUN<134>
  PIN VGRUN<130>
    DIRECTION INOUT ;
    USE SIGNAL ;
    PORT
      LAYER METAL3 ;
        RECT 2027.43 1687.57 2028.23 1688.37 ;
    END
  END VGRUN<130>
  PIN VGRUN<126>
    DIRECTION INOUT ;
    USE SIGNAL ;
    PORT
      LAYER METAL3 ;
        RECT 1972.51 1687.57 1973.31 1688.37 ;
    END
  END VGRUN<126>
  PIN VGRUN<122>
    DIRECTION INOUT ;
    USE SIGNAL ;
    PORT
      LAYER METAL3 ;
        RECT 1917.59 1687.57 1918.39 1688.37 ;
    END
  END VGRUN<122>
  PIN VGRUN<118>
    DIRECTION INOUT ;
    USE SIGNAL ;
    PORT
      LAYER METAL3 ;
        RECT 1862.67 1687.57 1863.47 1688.37 ;
    END
  END VGRUN<118>
  PIN VGRUN<114>
    DIRECTION INOUT ;
    USE SIGNAL ;
    PORT
      LAYER METAL3 ;
        RECT 1807.75 1687.57 1808.55 1688.37 ;
    END
  END VGRUN<114>
  PIN VGRUN<110>
    DIRECTION INOUT ;
    USE SIGNAL ;
    PORT
      LAYER METAL3 ;
        RECT 1752.83 1687.57 1753.63 1688.37 ;
    END
  END VGRUN<110>
  PIN VGRUN<106>
    DIRECTION INOUT ;
    USE SIGNAL ;
    PORT
      LAYER METAL3 ;
        RECT 1697.91 1687.57 1698.71 1688.37 ;
    END
  END VGRUN<106>
  PIN VGRUN<102>
    DIRECTION INOUT ;
    USE SIGNAL ;
    PORT
      LAYER METAL3 ;
        RECT 1642.99 1687.57 1643.79 1688.37 ;
    END
  END VGRUN<102>
  PIN VGRUN<98>
    DIRECTION INOUT ;
    USE SIGNAL ;
    PORT
      LAYER METAL3 ;
        RECT 1588.07 1687.57 1588.87 1688.37 ;
    END
  END VGRUN<98>
  PIN VGRUN<94>
    DIRECTION INOUT ;
    USE SIGNAL ;
    PORT
      LAYER METAL3 ;
        RECT 1533.15 1687.57 1533.95 1688.37 ;
    END
  END VGRUN<94>
  PIN VGRUN<90>
    DIRECTION INOUT ;
    USE SIGNAL ;
    PORT
      LAYER METAL3 ;
        RECT 1478.23 1687.57 1479.03 1688.37 ;
    END
  END VGRUN<90>
  PIN VGRUN<86>
    DIRECTION INOUT ;
    USE SIGNAL ;
    PORT
      LAYER METAL3 ;
        RECT 1423.31 1687.57 1424.11 1688.37 ;
    END
  END VGRUN<86>
  PIN VGRUN<82>
    DIRECTION INOUT ;
    USE SIGNAL ;
    PORT
      LAYER METAL3 ;
        RECT 1368.39 1687.57 1369.19 1688.37 ;
    END
  END VGRUN<82>
  PIN VGRUN<78>
    DIRECTION INOUT ;
    USE SIGNAL ;
    PORT
      LAYER METAL3 ;
        RECT 1313.47 1687.57 1314.27 1688.37 ;
    END
  END VGRUN<78>
  PIN VGRUN<74>
    DIRECTION INOUT ;
    USE SIGNAL ;
    PORT
      LAYER METAL3 ;
        RECT 1258.55 1687.57 1259.35 1688.37 ;
    END
  END VGRUN<74>
  PIN VGRUN<70>
    DIRECTION INOUT ;
    USE SIGNAL ;
    PORT
      LAYER METAL3 ;
        RECT 1203.63 1687.57 1204.43 1688.37 ;
    END
  END VGRUN<70>
  PIN VGRUN<66>
    DIRECTION INOUT ;
    USE SIGNAL ;
    PORT
      LAYER METAL3 ;
        RECT 1148.71 1687.57 1149.51 1688.37 ;
    END
  END VGRUN<66>
  PIN VGRUN<62>
    DIRECTION INOUT ;
    USE SIGNAL ;
    PORT
      LAYER METAL3 ;
        RECT 1093.79 1687.57 1094.59 1688.37 ;
    END
  END VGRUN<62>
  PIN VGRUN<58>
    DIRECTION INOUT ;
    USE SIGNAL ;
    PORT
      LAYER METAL3 ;
        RECT 1038.87 1687.57 1039.67 1688.37 ;
    END
  END VGRUN<58>
  PIN VGRUN<54>
    DIRECTION INOUT ;
    USE SIGNAL ;
    PORT
      LAYER METAL3 ;
        RECT 983.95 1687.57 984.75 1688.37 ;
    END
  END VGRUN<54>
  PIN VGRUN<50>
    DIRECTION INOUT ;
    USE SIGNAL ;
    PORT
      LAYER METAL3 ;
        RECT 929.03 1687.57 929.83 1688.37 ;
    END
  END VGRUN<50>
  PIN VGRUN<46>
    DIRECTION INOUT ;
    USE SIGNAL ;
    PORT
      LAYER METAL3 ;
        RECT 874.11 1687.57 874.91 1688.37 ;
    END
  END VGRUN<46>
  PIN VGRUN<42>
    DIRECTION INOUT ;
    USE SIGNAL ;
    PORT
      LAYER METAL3 ;
        RECT 819.19 1687.57 819.99 1688.37 ;
    END
  END VGRUN<42>
  PIN VGRUN<38>
    DIRECTION INOUT ;
    USE SIGNAL ;
    PORT
      LAYER METAL3 ;
        RECT 764.27 1687.57 765.07 1688.37 ;
    END
  END VGRUN<38>
  PIN VGRUN<34>
    DIRECTION INOUT ;
    USE SIGNAL ;
    PORT
      LAYER METAL3 ;
        RECT 709.35 1687.57 710.15 1688.37 ;
    END
  END VGRUN<34>
  PIN VGRUN<30>
    DIRECTION INOUT ;
    USE SIGNAL ;
    PORT
      LAYER METAL3 ;
        RECT 654.43 1687.57 655.23 1688.37 ;
    END
  END VGRUN<30>
  PIN VGRUN<26>
    DIRECTION INOUT ;
    USE SIGNAL ;
    PORT
      LAYER METAL3 ;
        RECT 599.51 1687.57 600.31 1688.37 ;
    END
  END VGRUN<26>
  PIN VGRUN<22>
    DIRECTION INOUT ;
    USE SIGNAL ;
    PORT
      LAYER METAL3 ;
        RECT 544.59 1687.57 545.39 1688.37 ;
    END
  END VGRUN<22>
  PIN VGRUN<18>
    DIRECTION INOUT ;
    USE SIGNAL ;
    PORT
      LAYER METAL3 ;
        RECT 489.67 1687.57 490.47 1688.37 ;
    END
  END VGRUN<18>
  PIN VGRUN<14>
    DIRECTION INOUT ;
    USE SIGNAL ;
    PORT
      LAYER METAL3 ;
        RECT 434.75 1687.57 435.55 1688.37 ;
    END
  END VGRUN<14>
  PIN VGRUN<10>
    DIRECTION INOUT ;
    USE SIGNAL ;
    PORT
      LAYER METAL3 ;
        RECT 379.83 1687.57 380.63 1688.37 ;
    END
  END VGRUN<10>
  PIN VGRUN<6>
    DIRECTION INOUT ;
    USE SIGNAL ;
    PORT
      LAYER METAL3 ;
        RECT 324.91 1687.57 325.71 1688.37 ;
    END
  END VGRUN<6>
  PIN VGRUN<2>
    DIRECTION INOUT ;
    USE SIGNAL ;
    PORT
      LAYER METAL3 ;
        RECT 269.99 1687.57 270.79 1688.37 ;
    END
  END VGRUN<2>
  PIN VGRUN<277>
    DIRECTION INOUT ;
    USE SIGNAL ;
    PORT
      LAYER METAL3 ;
        RECT 4041.97 1687.57 4042.77 1688.37 ;
    END
  END VGRUN<277>
  PIN VGRUN<273>
    DIRECTION INOUT ;
    USE SIGNAL ;
    PORT
      LAYER METAL3 ;
        RECT 3987.05 1687.57 3987.85 1688.37 ;
    END
  END VGRUN<273>
  PIN VGRUN<269>
    DIRECTION INOUT ;
    USE SIGNAL ;
    PORT
      LAYER METAL3 ;
        RECT 3932.13 1687.57 3932.93 1688.37 ;
    END
  END VGRUN<269>
  PIN VGRUN<265>
    DIRECTION INOUT ;
    USE SIGNAL ;
    PORT
      LAYER METAL3 ;
        RECT 3877.21 1687.57 3878.01 1688.37 ;
    END
  END VGRUN<265>
  PIN VGRUN<261>
    DIRECTION INOUT ;
    USE SIGNAL ;
    PORT
      LAYER METAL3 ;
        RECT 3822.29 1687.57 3823.09 1688.37 ;
    END
  END VGRUN<261>
  PIN VGRUN<257>
    DIRECTION INOUT ;
    USE SIGNAL ;
    PORT
      LAYER METAL3 ;
        RECT 3767.37 1687.57 3768.17 1688.37 ;
    END
  END VGRUN<257>
  PIN VGRUN<253>
    DIRECTION INOUT ;
    USE SIGNAL ;
    PORT
      LAYER METAL3 ;
        RECT 3712.45 1687.57 3713.25 1688.37 ;
    END
  END VGRUN<253>
  PIN VGRUN<249>
    DIRECTION INOUT ;
    USE SIGNAL ;
    PORT
      LAYER METAL3 ;
        RECT 3657.53 1687.57 3658.33 1688.37 ;
    END
  END VGRUN<249>
  PIN VGRUN<245>
    DIRECTION INOUT ;
    USE SIGNAL ;
    PORT
      LAYER METAL3 ;
        RECT 3602.61 1687.57 3603.41 1688.37 ;
    END
  END VGRUN<245>
  PIN VGRUN<241>
    DIRECTION INOUT ;
    USE SIGNAL ;
    PORT
      LAYER METAL3 ;
        RECT 3547.69 1687.57 3548.49 1688.37 ;
    END
  END VGRUN<241>
  PIN VGRUN<237>
    DIRECTION INOUT ;
    USE SIGNAL ;
    PORT
      LAYER METAL3 ;
        RECT 3492.77 1687.57 3493.57 1688.37 ;
    END
  END VGRUN<237>
  PIN VGRUN<233>
    DIRECTION INOUT ;
    USE SIGNAL ;
    PORT
      LAYER METAL3 ;
        RECT 3437.85 1687.57 3438.65 1688.37 ;
    END
  END VGRUN<233>
  PIN VGRUN<229>
    DIRECTION INOUT ;
    USE SIGNAL ;
    PORT
      LAYER METAL3 ;
        RECT 3382.93 1687.57 3383.73 1688.37 ;
    END
  END VGRUN<229>
  PIN VGRUN<225>
    DIRECTION INOUT ;
    USE SIGNAL ;
    PORT
      LAYER METAL3 ;
        RECT 3328.01 1687.57 3328.81 1688.37 ;
    END
  END VGRUN<225>
  PIN VGRUN<221>
    DIRECTION INOUT ;
    USE SIGNAL ;
    PORT
      LAYER METAL3 ;
        RECT 3273.09 1687.57 3273.89 1688.37 ;
    END
  END VGRUN<221>
  PIN VGRUN<217>
    DIRECTION INOUT ;
    USE SIGNAL ;
    PORT
      LAYER METAL3 ;
        RECT 3218.17 1687.57 3218.97 1688.37 ;
    END
  END VGRUN<217>
  PIN VGRUN<213>
    DIRECTION INOUT ;
    USE SIGNAL ;
    PORT
      LAYER METAL3 ;
        RECT 3163.25 1687.57 3164.05 1688.37 ;
    END
  END VGRUN<213>
  PIN VGRUN<209>
    DIRECTION INOUT ;
    USE SIGNAL ;
    PORT
      LAYER METAL3 ;
        RECT 3108.33 1687.57 3109.13 1688.37 ;
    END
  END VGRUN<209>
  PIN VGRUN<205>
    DIRECTION INOUT ;
    USE SIGNAL ;
    PORT
      LAYER METAL3 ;
        RECT 3053.41 1687.57 3054.21 1688.37 ;
    END
  END VGRUN<205>
  PIN VGRUN<201>
    DIRECTION INOUT ;
    USE SIGNAL ;
    PORT
      LAYER METAL3 ;
        RECT 2998.49 1687.57 2999.29 1688.37 ;
    END
  END VGRUN<201>
  PIN VGRUN<197>
    DIRECTION INOUT ;
    USE SIGNAL ;
    PORT
      LAYER METAL3 ;
        RECT 2943.57 1687.57 2944.37 1688.37 ;
    END
  END VGRUN<197>
  PIN VGRUN<193>
    DIRECTION INOUT ;
    USE SIGNAL ;
    PORT
      LAYER METAL3 ;
        RECT 2888.65 1687.57 2889.45 1688.37 ;
    END
  END VGRUN<193>
  PIN VGRUN<189>
    DIRECTION INOUT ;
    USE SIGNAL ;
    PORT
      LAYER METAL3 ;
        RECT 2833.73 1687.57 2834.53 1688.37 ;
    END
  END VGRUN<189>
  PIN VGRUN<185>
    DIRECTION INOUT ;
    USE SIGNAL ;
    PORT
      LAYER METAL3 ;
        RECT 2778.81 1687.57 2779.61 1688.37 ;
    END
  END VGRUN<185>
  PIN VGRUN<181>
    DIRECTION INOUT ;
    USE SIGNAL ;
    PORT
      LAYER METAL3 ;
        RECT 2723.89 1687.57 2724.69 1688.37 ;
    END
  END VGRUN<181>
  PIN VGRUN<177>
    DIRECTION INOUT ;
    USE SIGNAL ;
    PORT
      LAYER METAL3 ;
        RECT 2668.97 1687.57 2669.77 1688.37 ;
    END
  END VGRUN<177>
  PIN VGRUN<173>
    DIRECTION INOUT ;
    USE SIGNAL ;
    PORT
      LAYER METAL3 ;
        RECT 2614.05 1687.57 2614.85 1688.37 ;
    END
  END VGRUN<173>
  PIN VGRUN<169>
    DIRECTION INOUT ;
    USE SIGNAL ;
    PORT
      LAYER METAL3 ;
        RECT 2559.13 1687.57 2559.93 1688.37 ;
    END
  END VGRUN<169>
  PIN VGRUN<165>
    DIRECTION INOUT ;
    USE SIGNAL ;
    PORT
      LAYER METAL3 ;
        RECT 2504.21 1687.57 2505.01 1688.37 ;
    END
  END VGRUN<165>
  PIN VGRUN<161>
    DIRECTION INOUT ;
    USE SIGNAL ;
    PORT
      LAYER METAL3 ;
        RECT 2449.29 1687.57 2450.09 1688.37 ;
    END
  END VGRUN<161>
  PIN VGRUN<157>
    DIRECTION INOUT ;
    USE SIGNAL ;
    PORT
      LAYER METAL3 ;
        RECT 2394.37 1687.57 2395.17 1688.37 ;
    END
  END VGRUN<157>
  PIN VGRUN<153>
    DIRECTION INOUT ;
    USE SIGNAL ;
    PORT
      LAYER METAL3 ;
        RECT 2339.45 1687.57 2340.25 1688.37 ;
    END
  END VGRUN<153>
  PIN VGRUN<149>
    DIRECTION INOUT ;
    USE SIGNAL ;
    PORT
      LAYER METAL3 ;
        RECT 2284.53 1687.57 2285.33 1688.37 ;
    END
  END VGRUN<149>
  PIN VGRUN<145>
    DIRECTION INOUT ;
    USE SIGNAL ;
    PORT
      LAYER METAL3 ;
        RECT 2229.61 1687.57 2230.41 1688.37 ;
    END
  END VGRUN<145>
  PIN VGRUN<141>
    DIRECTION INOUT ;
    USE SIGNAL ;
    PORT
      LAYER METAL3 ;
        RECT 2174.69 1687.57 2175.49 1688.37 ;
    END
  END VGRUN<141>
  PIN VGRUN<137>
    DIRECTION INOUT ;
    USE SIGNAL ;
    PORT
      LAYER METAL3 ;
        RECT 2119.77 1687.57 2120.57 1688.37 ;
    END
  END VGRUN<137>
  PIN VGRUN<133>
    DIRECTION INOUT ;
    USE SIGNAL ;
    PORT
      LAYER METAL3 ;
        RECT 2064.85 1687.57 2065.65 1688.37 ;
    END
  END VGRUN<133>
  PIN VGRUN<129>
    DIRECTION INOUT ;
    USE SIGNAL ;
    PORT
      LAYER METAL3 ;
        RECT 2009.93 1687.57 2010.73 1688.37 ;
    END
  END VGRUN<129>
  PIN VGRUN<125>
    DIRECTION INOUT ;
    USE SIGNAL ;
    PORT
      LAYER METAL3 ;
        RECT 1955.01 1687.57 1955.81 1688.37 ;
    END
  END VGRUN<125>
  PIN VGRUN<121>
    DIRECTION INOUT ;
    USE SIGNAL ;
    PORT
      LAYER METAL3 ;
        RECT 1900.09 1687.57 1900.89 1688.37 ;
    END
  END VGRUN<121>
  PIN VGRUN<117>
    DIRECTION INOUT ;
    USE SIGNAL ;
    PORT
      LAYER METAL3 ;
        RECT 1845.17 1687.57 1845.97 1688.37 ;
    END
  END VGRUN<117>
  PIN VGRUN<113>
    DIRECTION INOUT ;
    USE SIGNAL ;
    PORT
      LAYER METAL3 ;
        RECT 1790.25 1687.57 1791.05 1688.37 ;
    END
  END VGRUN<113>
  PIN VGRUN<109>
    DIRECTION INOUT ;
    USE SIGNAL ;
    PORT
      LAYER METAL3 ;
        RECT 1735.33 1687.57 1736.13 1688.37 ;
    END
  END VGRUN<109>
  PIN VGRUN<105>
    DIRECTION INOUT ;
    USE SIGNAL ;
    PORT
      LAYER METAL3 ;
        RECT 1680.41 1687.57 1681.21 1688.37 ;
    END
  END VGRUN<105>
  PIN VGRUN<101>
    DIRECTION INOUT ;
    USE SIGNAL ;
    PORT
      LAYER METAL3 ;
        RECT 1625.49 1687.57 1626.29 1688.37 ;
    END
  END VGRUN<101>
  PIN VGRUN<97>
    DIRECTION INOUT ;
    USE SIGNAL ;
    PORT
      LAYER METAL3 ;
        RECT 1570.57 1687.57 1571.37 1688.37 ;
    END
  END VGRUN<97>
  PIN VGRUN<93>
    DIRECTION INOUT ;
    USE SIGNAL ;
    PORT
      LAYER METAL3 ;
        RECT 1515.65 1687.57 1516.45 1688.37 ;
    END
  END VGRUN<93>
  PIN VGRUN<89>
    DIRECTION INOUT ;
    USE SIGNAL ;
    PORT
      LAYER METAL3 ;
        RECT 1460.73 1687.57 1461.53 1688.37 ;
    END
  END VGRUN<89>
  PIN VGRUN<85>
    DIRECTION INOUT ;
    USE SIGNAL ;
    PORT
      LAYER METAL3 ;
        RECT 1405.81 1687.57 1406.61 1688.37 ;
    END
  END VGRUN<85>
  PIN VGRUN<81>
    DIRECTION INOUT ;
    USE SIGNAL ;
    PORT
      LAYER METAL3 ;
        RECT 1350.89 1687.57 1351.69 1688.37 ;
    END
  END VGRUN<81>
  PIN VGRUN<77>
    DIRECTION INOUT ;
    USE SIGNAL ;
    PORT
      LAYER METAL3 ;
        RECT 1295.97 1687.57 1296.77 1688.37 ;
    END
  END VGRUN<77>
  PIN VGRUN<73>
    DIRECTION INOUT ;
    USE SIGNAL ;
    PORT
      LAYER METAL3 ;
        RECT 1241.05 1687.57 1241.85 1688.37 ;
    END
  END VGRUN<73>
  PIN VGRUN<69>
    DIRECTION INOUT ;
    USE SIGNAL ;
    PORT
      LAYER METAL3 ;
        RECT 1186.13 1687.57 1186.93 1688.37 ;
    END
  END VGRUN<69>
  PIN VGRUN<65>
    DIRECTION INOUT ;
    USE SIGNAL ;
    PORT
      LAYER METAL3 ;
        RECT 1131.21 1687.57 1132.01 1688.37 ;
    END
  END VGRUN<65>
  PIN VGRUN<61>
    DIRECTION INOUT ;
    USE SIGNAL ;
    PORT
      LAYER METAL3 ;
        RECT 1076.29 1687.57 1077.09 1688.37 ;
    END
  END VGRUN<61>
  PIN VGRUN<57>
    DIRECTION INOUT ;
    USE SIGNAL ;
    PORT
      LAYER METAL3 ;
        RECT 1021.37 1687.57 1022.17 1688.37 ;
    END
  END VGRUN<57>
  PIN VGRUN<53>
    DIRECTION INOUT ;
    USE SIGNAL ;
    PORT
      LAYER METAL3 ;
        RECT 966.45 1687.57 967.25 1688.37 ;
    END
  END VGRUN<53>
  PIN VGRUN<49>
    DIRECTION INOUT ;
    USE SIGNAL ;
    PORT
      LAYER METAL3 ;
        RECT 911.53 1687.57 912.33 1688.37 ;
    END
  END VGRUN<49>
  PIN VGRUN<45>
    DIRECTION INOUT ;
    USE SIGNAL ;
    PORT
      LAYER METAL3 ;
        RECT 856.61 1687.57 857.41 1688.37 ;
    END
  END VGRUN<45>
  PIN VGRUN<41>
    DIRECTION INOUT ;
    USE SIGNAL ;
    PORT
      LAYER METAL3 ;
        RECT 801.69 1687.57 802.49 1688.37 ;
    END
  END VGRUN<41>
  PIN VGRUN<37>
    DIRECTION INOUT ;
    USE SIGNAL ;
    PORT
      LAYER METAL3 ;
        RECT 746.77 1687.57 747.57 1688.37 ;
    END
  END VGRUN<37>
  PIN VGRUN<33>
    DIRECTION INOUT ;
    USE SIGNAL ;
    PORT
      LAYER METAL3 ;
        RECT 691.85 1687.57 692.65 1688.37 ;
    END
  END VGRUN<33>
  PIN VGRUN<29>
    DIRECTION INOUT ;
    USE SIGNAL ;
    PORT
      LAYER METAL3 ;
        RECT 636.93 1687.57 637.73 1688.37 ;
    END
  END VGRUN<29>
  PIN VGRUN<25>
    DIRECTION INOUT ;
    USE SIGNAL ;
    PORT
      LAYER METAL3 ;
        RECT 582.01 1687.57 582.81 1688.37 ;
    END
  END VGRUN<25>
  PIN VGRUN<21>
    DIRECTION INOUT ;
    USE SIGNAL ;
    PORT
      LAYER METAL3 ;
        RECT 527.09 1687.57 527.89 1688.37 ;
    END
  END VGRUN<21>
  PIN VGRUN<17>
    DIRECTION INOUT ;
    USE SIGNAL ;
    PORT
      LAYER METAL3 ;
        RECT 472.17 1687.57 472.97 1688.37 ;
    END
  END VGRUN<17>
  PIN VGRUN<13>
    DIRECTION INOUT ;
    USE SIGNAL ;
    PORT
      LAYER METAL3 ;
        RECT 417.25 1687.57 418.05 1688.37 ;
    END
  END VGRUN<13>
  PIN VGRUN<9>
    DIRECTION INOUT ;
    USE SIGNAL ;
    PORT
      LAYER METAL3 ;
        RECT 362.33 1687.57 363.13 1688.37 ;
    END
  END VGRUN<9>
  PIN VGRUN<5>
    DIRECTION INOUT ;
    USE SIGNAL ;
    PORT
      LAYER METAL3 ;
        RECT 307.41 1687.57 308.21 1688.37 ;
    END
  END VGRUN<5>
  PIN VGRUN<1>
    DIRECTION INOUT ;
    USE SIGNAL ;
    PORT
      LAYER METAL3 ;
        RECT 252.49 1687.57 253.29 1688.37 ;
    END
  END VGRUN<1>
  PIN VGRUN<276>
    DIRECTION INOUT ;
    USE SIGNAL ;
    PORT
      LAYER METAL3 ;
        RECT 4039.87 1687.57 4040.67 1688.37 ;
    END
  END VGRUN<276>
  PIN VGRUN<272>
    DIRECTION INOUT ;
    USE SIGNAL ;
    PORT
      LAYER METAL3 ;
        RECT 3984.95 1687.57 3985.75 1688.37 ;
    END
  END VGRUN<272>
  PIN VGRUN<268>
    DIRECTION INOUT ;
    USE SIGNAL ;
    PORT
      LAYER METAL3 ;
        RECT 3930.03 1687.57 3930.83 1688.37 ;
    END
  END VGRUN<268>
  PIN VGRUN<264>
    DIRECTION INOUT ;
    USE SIGNAL ;
    PORT
      LAYER METAL3 ;
        RECT 3875.11 1687.57 3875.91 1688.37 ;
    END
  END VGRUN<264>
  PIN VGRUN<260>
    DIRECTION INOUT ;
    USE SIGNAL ;
    PORT
      LAYER METAL3 ;
        RECT 3820.19 1687.57 3820.99 1688.37 ;
    END
  END VGRUN<260>
  PIN VGRUN<256>
    DIRECTION INOUT ;
    USE SIGNAL ;
    PORT
      LAYER METAL3 ;
        RECT 3765.27 1687.57 3766.07 1688.37 ;
    END
  END VGRUN<256>
  PIN VGRUN<252>
    DIRECTION INOUT ;
    USE SIGNAL ;
    PORT
      LAYER METAL3 ;
        RECT 3710.35 1687.57 3711.15 1688.37 ;
    END
  END VGRUN<252>
  PIN VGRUN<248>
    DIRECTION INOUT ;
    USE SIGNAL ;
    PORT
      LAYER METAL3 ;
        RECT 3655.43 1687.57 3656.23 1688.37 ;
    END
  END VGRUN<248>
  PIN VGRUN<244>
    DIRECTION INOUT ;
    USE SIGNAL ;
    PORT
      LAYER METAL3 ;
        RECT 3600.51 1687.57 3601.31 1688.37 ;
    END
  END VGRUN<244>
  PIN VGRUN<240>
    DIRECTION INOUT ;
    USE SIGNAL ;
    PORT
      LAYER METAL3 ;
        RECT 3545.59 1687.57 3546.39 1688.37 ;
    END
  END VGRUN<240>
  PIN VGRUN<236>
    DIRECTION INOUT ;
    USE SIGNAL ;
    PORT
      LAYER METAL3 ;
        RECT 3490.67 1687.57 3491.47 1688.37 ;
    END
  END VGRUN<236>
  PIN VGRUN<232>
    DIRECTION INOUT ;
    USE SIGNAL ;
    PORT
      LAYER METAL3 ;
        RECT 3435.75 1687.57 3436.55 1688.37 ;
    END
  END VGRUN<232>
  PIN VGRUN<228>
    DIRECTION INOUT ;
    USE SIGNAL ;
    PORT
      LAYER METAL3 ;
        RECT 3380.83 1687.57 3381.63 1688.37 ;
    END
  END VGRUN<228>
  PIN VGRUN<224>
    DIRECTION INOUT ;
    USE SIGNAL ;
    PORT
      LAYER METAL3 ;
        RECT 3325.91 1687.57 3326.71 1688.37 ;
    END
  END VGRUN<224>
  PIN VGRUN<220>
    DIRECTION INOUT ;
    USE SIGNAL ;
    PORT
      LAYER METAL3 ;
        RECT 3270.99 1687.57 3271.79 1688.37 ;
    END
  END VGRUN<220>
  PIN VGRUN<216>
    DIRECTION INOUT ;
    USE SIGNAL ;
    PORT
      LAYER METAL3 ;
        RECT 3216.07 1687.57 3216.87 1688.37 ;
    END
  END VGRUN<216>
  PIN VGRUN<212>
    DIRECTION INOUT ;
    USE SIGNAL ;
    PORT
      LAYER METAL3 ;
        RECT 3161.15 1687.57 3161.95 1688.37 ;
    END
  END VGRUN<212>
  PIN VGRUN<208>
    DIRECTION INOUT ;
    USE SIGNAL ;
    PORT
      LAYER METAL3 ;
        RECT 3106.23 1687.57 3107.03 1688.37 ;
    END
  END VGRUN<208>
  PIN VGRUN<204>
    DIRECTION INOUT ;
    USE SIGNAL ;
    PORT
      LAYER METAL3 ;
        RECT 3051.31 1687.57 3052.11 1688.37 ;
    END
  END VGRUN<204>
  PIN VGRUN<200>
    DIRECTION INOUT ;
    USE SIGNAL ;
    PORT
      LAYER METAL3 ;
        RECT 2996.39 1687.57 2997.19 1688.37 ;
    END
  END VGRUN<200>
  PIN VGRUN<196>
    DIRECTION INOUT ;
    USE SIGNAL ;
    PORT
      LAYER METAL3 ;
        RECT 2941.47 1687.57 2942.27 1688.37 ;
    END
  END VGRUN<196>
  PIN VGRUN<192>
    DIRECTION INOUT ;
    USE SIGNAL ;
    PORT
      LAYER METAL3 ;
        RECT 2886.55 1687.57 2887.35 1688.37 ;
    END
  END VGRUN<192>
  PIN VGRUN<188>
    DIRECTION INOUT ;
    USE SIGNAL ;
    PORT
      LAYER METAL3 ;
        RECT 2831.63 1687.57 2832.43 1688.37 ;
    END
  END VGRUN<188>
  PIN VGRUN<184>
    DIRECTION INOUT ;
    USE SIGNAL ;
    PORT
      LAYER METAL3 ;
        RECT 2776.71 1687.57 2777.51 1688.37 ;
    END
  END VGRUN<184>
  PIN VGRUN<180>
    DIRECTION INOUT ;
    USE SIGNAL ;
    PORT
      LAYER METAL3 ;
        RECT 2721.79 1687.57 2722.59 1688.37 ;
    END
  END VGRUN<180>
  PIN VGRUN<176>
    DIRECTION INOUT ;
    USE SIGNAL ;
    PORT
      LAYER METAL3 ;
        RECT 2666.87 1687.57 2667.67 1688.37 ;
    END
  END VGRUN<176>
  PIN VGRUN<172>
    DIRECTION INOUT ;
    USE SIGNAL ;
    PORT
      LAYER METAL3 ;
        RECT 2611.95 1687.57 2612.75 1688.37 ;
    END
  END VGRUN<172>
  PIN VGRUN<168>
    DIRECTION INOUT ;
    USE SIGNAL ;
    PORT
      LAYER METAL3 ;
        RECT 2557.03 1687.57 2557.83 1688.37 ;
    END
  END VGRUN<168>
  PIN VGRUN<164>
    DIRECTION INOUT ;
    USE SIGNAL ;
    PORT
      LAYER METAL3 ;
        RECT 2502.11 1687.57 2502.91 1688.37 ;
    END
  END VGRUN<164>
  PIN VGRUN<160>
    DIRECTION INOUT ;
    USE SIGNAL ;
    PORT
      LAYER METAL3 ;
        RECT 2447.19 1687.57 2447.99 1688.37 ;
    END
  END VGRUN<160>
  PIN VGRUN<156>
    DIRECTION INOUT ;
    USE SIGNAL ;
    PORT
      LAYER METAL3 ;
        RECT 2392.27 1687.57 2393.07 1688.37 ;
    END
  END VGRUN<156>
  PIN VGRUN<152>
    DIRECTION INOUT ;
    USE SIGNAL ;
    PORT
      LAYER METAL3 ;
        RECT 2337.35 1687.57 2338.15 1688.37 ;
    END
  END VGRUN<152>
  PIN VGRUN<148>
    DIRECTION INOUT ;
    USE SIGNAL ;
    PORT
      LAYER METAL3 ;
        RECT 2282.43 1687.57 2283.23 1688.37 ;
    END
  END VGRUN<148>
  PIN VGRUN<144>
    DIRECTION INOUT ;
    USE SIGNAL ;
    PORT
      LAYER METAL3 ;
        RECT 2227.51 1687.57 2228.31 1688.37 ;
    END
  END VGRUN<144>
  PIN VGRUN<140>
    DIRECTION INOUT ;
    USE SIGNAL ;
    PORT
      LAYER METAL3 ;
        RECT 2172.59 1687.57 2173.39 1688.37 ;
    END
  END VGRUN<140>
  PIN VGRUN<136>
    DIRECTION INOUT ;
    USE SIGNAL ;
    PORT
      LAYER METAL3 ;
        RECT 2117.67 1687.57 2118.47 1688.37 ;
    END
  END VGRUN<136>
  PIN VGRUN<132>
    DIRECTION INOUT ;
    USE SIGNAL ;
    PORT
      LAYER METAL3 ;
        RECT 2062.75 1687.57 2063.55 1688.37 ;
    END
  END VGRUN<132>
  PIN VGRUN<128>
    DIRECTION INOUT ;
    USE SIGNAL ;
    PORT
      LAYER METAL3 ;
        RECT 2007.83 1687.57 2008.63 1688.37 ;
    END
  END VGRUN<128>
  PIN VGRUN<124>
    DIRECTION INOUT ;
    USE SIGNAL ;
    PORT
      LAYER METAL3 ;
        RECT 1952.91 1687.57 1953.71 1688.37 ;
    END
  END VGRUN<124>
  PIN VGRUN<120>
    DIRECTION INOUT ;
    USE SIGNAL ;
    PORT
      LAYER METAL3 ;
        RECT 1897.99 1687.57 1898.79 1688.37 ;
    END
  END VGRUN<120>
  PIN VGRUN<116>
    DIRECTION INOUT ;
    USE SIGNAL ;
    PORT
      LAYER METAL3 ;
        RECT 1843.07 1687.57 1843.87 1688.37 ;
    END
  END VGRUN<116>
  PIN VGRUN<112>
    DIRECTION INOUT ;
    USE SIGNAL ;
    PORT
      LAYER METAL3 ;
        RECT 1788.15 1687.57 1788.95 1688.37 ;
    END
  END VGRUN<112>
  PIN VGRUN<108>
    DIRECTION INOUT ;
    USE SIGNAL ;
    PORT
      LAYER METAL3 ;
        RECT 1733.23 1687.57 1734.03 1688.37 ;
    END
  END VGRUN<108>
  PIN VGRUN<104>
    DIRECTION INOUT ;
    USE SIGNAL ;
    PORT
      LAYER METAL3 ;
        RECT 1678.31 1687.57 1679.11 1688.37 ;
    END
  END VGRUN<104>
  PIN VGRUN<100>
    DIRECTION INOUT ;
    USE SIGNAL ;
    PORT
      LAYER METAL3 ;
        RECT 1623.39 1687.57 1624.19 1688.37 ;
    END
  END VGRUN<100>
  PIN VGRUN<96>
    DIRECTION INOUT ;
    USE SIGNAL ;
    PORT
      LAYER METAL3 ;
        RECT 1568.47 1687.57 1569.27 1688.37 ;
    END
  END VGRUN<96>
  PIN VGRUN<92>
    DIRECTION INOUT ;
    USE SIGNAL ;
    PORT
      LAYER METAL3 ;
        RECT 1513.55 1687.57 1514.35 1688.37 ;
    END
  END VGRUN<92>
  PIN VGRUN<88>
    DIRECTION INOUT ;
    USE SIGNAL ;
    PORT
      LAYER METAL3 ;
        RECT 1458.63 1687.57 1459.43 1688.37 ;
    END
  END VGRUN<88>
  PIN VGRUN<84>
    DIRECTION INOUT ;
    USE SIGNAL ;
    PORT
      LAYER METAL3 ;
        RECT 1403.71 1687.57 1404.51 1688.37 ;
    END
  END VGRUN<84>
  PIN VGRUN<80>
    DIRECTION INOUT ;
    USE SIGNAL ;
    PORT
      LAYER METAL3 ;
        RECT 1348.79 1687.57 1349.59 1688.37 ;
    END
  END VGRUN<80>
  PIN VGRUN<76>
    DIRECTION INOUT ;
    USE SIGNAL ;
    PORT
      LAYER METAL3 ;
        RECT 1293.87 1687.57 1294.67 1688.37 ;
    END
  END VGRUN<76>
  PIN VGRUN<72>
    DIRECTION INOUT ;
    USE SIGNAL ;
    PORT
      LAYER METAL3 ;
        RECT 1238.95 1687.57 1239.75 1688.37 ;
    END
  END VGRUN<72>
  PIN VGRUN<68>
    DIRECTION INOUT ;
    USE SIGNAL ;
    PORT
      LAYER METAL3 ;
        RECT 1184.03 1687.57 1184.83 1688.37 ;
    END
  END VGRUN<68>
  PIN VGRUN<64>
    DIRECTION INOUT ;
    USE SIGNAL ;
    PORT
      LAYER METAL3 ;
        RECT 1129.11 1687.57 1129.91 1688.37 ;
    END
  END VGRUN<64>
  PIN VGRUN<60>
    DIRECTION INOUT ;
    USE SIGNAL ;
    PORT
      LAYER METAL3 ;
        RECT 1074.19 1687.57 1074.99 1688.37 ;
    END
  END VGRUN<60>
  PIN VGRUN<56>
    DIRECTION INOUT ;
    USE SIGNAL ;
    PORT
      LAYER METAL3 ;
        RECT 1019.27 1687.57 1020.07 1688.37 ;
    END
  END VGRUN<56>
  PIN VGRUN<52>
    DIRECTION INOUT ;
    USE SIGNAL ;
    PORT
      LAYER METAL3 ;
        RECT 964.35 1687.57 965.15 1688.37 ;
    END
  END VGRUN<52>
  PIN VGRUN<48>
    DIRECTION INOUT ;
    USE SIGNAL ;
    PORT
      LAYER METAL3 ;
        RECT 909.43 1687.57 910.23 1688.37 ;
    END
  END VGRUN<48>
  PIN VGRUN<44>
    DIRECTION INOUT ;
    USE SIGNAL ;
    PORT
      LAYER METAL3 ;
        RECT 854.51 1687.57 855.31 1688.37 ;
    END
  END VGRUN<44>
  PIN VGRUN<40>
    DIRECTION INOUT ;
    USE SIGNAL ;
    PORT
      LAYER METAL3 ;
        RECT 799.59 1687.57 800.39 1688.37 ;
    END
  END VGRUN<40>
  PIN VGRUN<36>
    DIRECTION INOUT ;
    USE SIGNAL ;
    PORT
      LAYER METAL3 ;
        RECT 744.67 1687.57 745.47 1688.37 ;
    END
  END VGRUN<36>
  PIN VGRUN<32>
    DIRECTION INOUT ;
    USE SIGNAL ;
    PORT
      LAYER METAL3 ;
        RECT 689.75 1687.57 690.55 1688.37 ;
    END
  END VGRUN<32>
  PIN VGRUN<28>
    DIRECTION INOUT ;
    USE SIGNAL ;
    PORT
      LAYER METAL3 ;
        RECT 634.83 1687.57 635.63 1688.37 ;
    END
  END VGRUN<28>
  PIN VGRUN<24>
    DIRECTION INOUT ;
    USE SIGNAL ;
    PORT
      LAYER METAL3 ;
        RECT 579.91 1687.57 580.71 1688.37 ;
    END
  END VGRUN<24>
  PIN VGRUN<20>
    DIRECTION INOUT ;
    USE SIGNAL ;
    PORT
      LAYER METAL3 ;
        RECT 524.99 1687.57 525.79 1688.37 ;
    END
  END VGRUN<20>
  PIN VGRUN<16>
    DIRECTION INOUT ;
    USE SIGNAL ;
    PORT
      LAYER METAL3 ;
        RECT 470.07 1687.57 470.87 1688.37 ;
    END
  END VGRUN<16>
  PIN VGRUN<12>
    DIRECTION INOUT ;
    USE SIGNAL ;
    PORT
      LAYER METAL3 ;
        RECT 415.15 1687.57 415.95 1688.37 ;
    END
  END VGRUN<12>
  PIN VGRUN<8>
    DIRECTION INOUT ;
    USE SIGNAL ;
    PORT
      LAYER METAL3 ;
        RECT 360.23 1687.57 361.03 1688.37 ;
    END
  END VGRUN<8>
  PIN VGRUN<4>
    DIRECTION INOUT ;
    USE SIGNAL ;
    PORT
      LAYER METAL3 ;
        RECT 305.31 1687.57 306.11 1688.37 ;
    END
  END VGRUN<4>
  PIN VGRUN<0>
    DIRECTION INOUT ;
    USE SIGNAL ;
    PORT
      LAYER METAL3 ;
        RECT 250.39 1687.57 251.19 1688.37 ;
    END
  END VGRUN<0>
  PIN w_DrainEnable_WTA
    DIRECTION INOUT ;
    USE SIGNAL ;
    PORT
      LAYER METAL3 ;
        RECT 0.0 1632.57 2.8 1633.97 ;
    END
  END w_DrainEnable_WTA
  PIN w_Drainline_Run
    DIRECTION INOUT ;
    USE SIGNAL ;
    PORT
      LAYER METAL3 ;
        RECT 0.0 1646.57 2.8 1647.97 ;
    END
  END w_Drainline_Run
  PIN w_Drainline_Prog
    DIRECTION INOUT ;
    USE SIGNAL ;
    PORT
      LAYER METAL3 ;
        RECT 0.0 1660.57 2.8 1661.97 ;
    END
  END w_Drainline_Prog
  PIN w_DrainB<7>
    DIRECTION INOUT ;
    USE SIGNAL ;
    PORT
      LAYER METAL3 ;
        RECT 0.0 1674.57 2.8 1675.97 ;
    END
  END w_DrainB<7>
  PIN w_DrainB<6>
    DIRECTION INOUT ;
    USE SIGNAL ;
    PORT
      LAYER METAL3 ;
        RECT 0.0 1688.57 2.8 1689.97 ;
    END
  END w_DrainB<6>
  PIN w_DrainB<5>
    DIRECTION INOUT ;
    USE SIGNAL ;
    PORT
      LAYER METAL3 ;
        RECT 0.0 1702.57 2.8 1703.97 ;
    END
  END w_DrainB<5>
  PIN w_DrainB<4>
    DIRECTION INOUT ;
    USE SIGNAL ;
    PORT
      LAYER METAL3 ;
        RECT 0.0 1716.57 2.8 1717.97 ;
    END
  END w_DrainB<4>
  PIN w_DrainB<3>
    DIRECTION INOUT ;
    USE SIGNAL ;
    PORT
      LAYER METAL3 ;
        RECT 0.0 1730.57 2.8 1731.97 ;
    END
  END w_DrainB<3>
  PIN w_DrainB<2>
    DIRECTION INOUT ;
    USE SIGNAL ;
    PORT
      LAYER METAL3 ;
        RECT 0.0 1744.57 2.8 1745.97 ;
    END
  END w_DrainB<2>
  PIN w_DrainB<1>
    DIRECTION INOUT ;
    USE SIGNAL ;
    PORT
      LAYER METAL3 ;
        RECT 0.0 1758.57 2.8 1759.97 ;
    END
  END w_DrainB<1>
  PIN w_DrainB<0>
    DIRECTION INOUT ;
    USE SIGNAL ;
    PORT
      LAYER METAL3 ;
        RECT 0.0 1772.57 2.8 1773.97 ;
    END
  END w_DrainB<0>
  PIN s_vinj
    DIRECTION INOUT ;
    USE SIGNAL ;
    PORT
      LAYER METAL3 ;
        RECT 4442.2 0.0 4443.6 2.8 ;
    END
  END s_vinj
  PIN s_gnd
    DIRECTION INOUT ;
    USE SIGNAL ;
    PORT
      LAYER METAL3 ;
        RECT 4456.2 0.0 4457.6 2.8 ;
    END
  END s_gnd
  PIN e_RSTBar
    DIRECTION INOUT ;
    USE SIGNAL ;
    PORT
      LAYER METAL3 ;
        RECT 4482.8 1730.57 4485.6 1731.97 ;
    END
  END e_RSTBar
  PIN e_CLK
    DIRECTION INOUT ;
    USE SIGNAL ;
    PORT
      LAYER METAL3 ;
        RECT 4482.8 1744.57 4485.6 1745.97 ;
    END
  END e_CLK
  PIN e_Din
    DIRECTION INOUT ;
    USE SIGNAL ;
    PORT
      LAYER METAL3 ;
        RECT 4482.8 1758.57 4485.6 1759.97 ;
    END
  END e_Din
  PIN e_WTA_out
    DIRECTION INOUT ;
    USE SIGNAL ;
    PORT
      LAYER METAL3 ;
        RECT 4482.8 1772.57 4485.6 1773.97 ;
    END
  END e_WTA_out
  PIN n_GateEnable_WTA
    DIRECTION INOUT ;
    USE SIGNAL ;
    PORT
      LAYER METAL3 ;
        RECT 209.3 1785.17 210.7 1787.97 ;
    END
  END n_GateEnable_WTA
  PIN n_GateB<8>
    DIRECTION INOUT ;
    USE SIGNAL ;
    PORT
      LAYER METAL3 ;
        RECT 195.3 1785.17 196.7 1787.97 ;
    END
  END n_GateB<8>
  PIN n_GateB<7>
    DIRECTION INOUT ;
    USE SIGNAL ;
    PORT
      LAYER METAL3 ;
        RECT 181.3 1785.17 182.7 1787.97 ;
    END
  END n_GateB<7>
  PIN n_GateB<6>
    DIRECTION INOUT ;
    USE SIGNAL ;
    PORT
      LAYER METAL3 ;
        RECT 167.3 1785.17 168.7 1787.97 ;
    END
  END n_GateB<6>
  PIN n_GateB<5>
    DIRECTION INOUT ;
    USE SIGNAL ;
    PORT
      LAYER METAL3 ;
        RECT 153.3 1785.17 154.7 1787.97 ;
    END
  END n_GateB<5>
  PIN n_GateB<4>
    DIRECTION INOUT ;
    USE SIGNAL ;
    PORT
      LAYER METAL3 ;
        RECT 139.3 1785.17 140.7 1787.97 ;
    END
  END n_GateB<4>
  PIN n_GateB<3>
    DIRECTION INOUT ;
    USE SIGNAL ;
    PORT
      LAYER METAL3 ;
        RECT 125.3 1785.17 126.7 1787.97 ;
    END
  END n_GateB<3>
  PIN n_GateB<2>
    DIRECTION INOUT ;
    USE SIGNAL ;
    PORT
      LAYER METAL3 ;
        RECT 111.3 1785.17 112.7 1787.97 ;
    END
  END n_GateB<2>
  PIN n_GateB<1>
    DIRECTION INOUT ;
    USE SIGNAL ;
    PORT
      LAYER METAL3 ;
        RECT 97.3 1785.17 98.7 1787.97 ;
    END
  END n_GateB<1>
  PIN n_GateB<0>
    DIRECTION INOUT ;
    USE SIGNAL ;
    PORT
      LAYER METAL3 ;
        RECT 83.3 1785.17 84.7 1787.97 ;
    END
  END n_GateB<0>
  PIN n_vinj
    DIRECTION INOUT ;
    USE SIGNAL ;
    PORT
      LAYER METAL3 ;
        RECT 4442.2 1785.17 4443.6 1787.97 ;
    END
  END n_vinj
  PIN n_gnd
    DIRECTION INOUT ;
    USE SIGNAL ;
    PORT
      LAYER METAL3 ;
        RECT 4456.2 1785.17 4457.6 1787.97 ;
    END
  END n_gnd
  PIN n_AVDD
    DIRECTION INOUT ;
    USE SIGNAL ;
    PORT
      LAYER METAL3 ;
        RECT 69.3 1785.17 70.7 1787.97 ;
    END
  END n_AVDD
  PIN n_VTUN
    DIRECTION INOUT ;
    USE SIGNAL ;
    PORT
      LAYER METAL3 ;
        RECT 55.3 1785.17 56.7 1787.97 ;
    END
  END n_VTUN
  PIN n_VGPROG
    DIRECTION INOUT ;
    USE SIGNAL ;
    PORT
      LAYER METAL3 ;
        RECT 41.3 1785.17 42.7 1787.97 ;
    END
  END n_VGPROG
  PIN n_Run
    DIRECTION INOUT ;
    USE SIGNAL ;
    PORT
      LAYER METAL3 ;
        RECT 27.3 1785.17 28.7 1787.97 ;
    END
  END n_Run
  PIN n_Prog
    DIRECTION INOUT ;
    USE SIGNAL ;
    PORT
      LAYER METAL3 ;
        RECT 13.3 1785.17 14.7 1787.97 ;
    END
  END n_Prog
END VMMWTA

END LIBRARY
